VERSION 5.8 ;
BUSBITCHARS "[]" ;
DIVIDERCHAR "/" ;
UNITS
    DATABASE MICRONS 1000 ;
END UNITS

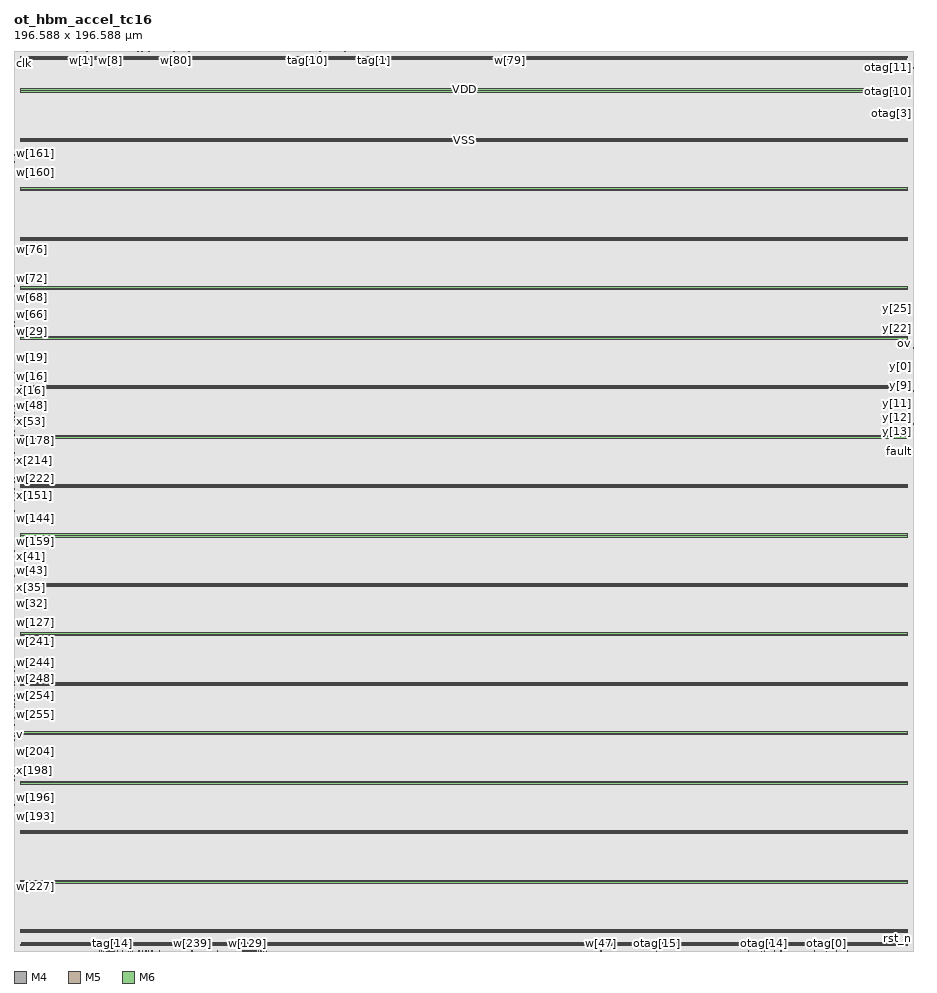
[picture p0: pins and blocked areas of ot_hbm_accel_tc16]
MACRO ot_hbm_accel_tc16
  FOREIGN ot_hbm_accel_tc16 0 0 ;
  CLASS BLOCK ;
  SIZE 196.588 BY 196.588 ;
  PIN clk
    DIRECTION INPUT ;
    USE SIGNAL ;
    PORT
      LAYER M4 ;
        RECT  0 193.824 0.084 193.848 ;
    END
  END clk
  PIN fault
    DIRECTION OUTPUT ;
    USE SIGNAL ;
    PORT
      LAYER M4 ;
        RECT  196.504 109.152 196.588 109.176 ;
    END
  END fault
  PIN first
    DIRECTION INPUT ;
    USE SIGNAL ;
    PORT
      LAYER M4 ;
        RECT  0 47.424 0.084 47.448 ;
    END
  END first
  PIN last
    DIRECTION INPUT ;
    USE SIGNAL ;
    PORT
      LAYER M4 ;
        RECT  0 47.616 0.084 47.64 ;
    END
  END last
  PIN otag[0]
    DIRECTION OUTPUT ;
    USE SIGNAL ;
    PORT
      LAYER M5 ;
        RECT  177.408 0 177.432 0.084 ;
    END
  END otag[0]
  PIN otag[10]
    DIRECTION OUTPUT ;
    USE SIGNAL ;
    PORT
      LAYER M4 ;
        RECT  196.504 187.68 196.588 187.704 ;
    END
  END otag[10]
  PIN otag[11]
    DIRECTION OUTPUT ;
    USE SIGNAL ;
    PORT
      LAYER M4 ;
        RECT  196.504 192.864 196.588 192.888 ;
    END
  END otag[11]
  PIN otag[12]
    DIRECTION OUTPUT ;
    USE SIGNAL ;
    PORT
      LAYER M5 ;
        RECT  174.816 0 174.84 0.084 ;
    END
  END otag[12]
  PIN otag[13]
    DIRECTION OUTPUT ;
    USE SIGNAL ;
    PORT
      LAYER M5 ;
        RECT  179.712 0 179.736 0.084 ;
    END
  END otag[13]
  PIN otag[14]
    DIRECTION OUTPUT ;
    USE SIGNAL ;
    PORT
      LAYER M5 ;
        RECT  163.872 0 163.896 0.084 ;
    END
  END otag[14]
  PIN otag[15]
    DIRECTION OUTPUT ;
    USE SIGNAL ;
    PORT
      LAYER M5 ;
        RECT  140.352 0 140.376 0.084 ;
    END
  END otag[15]
  PIN otag[1]
    DIRECTION OUTPUT ;
    USE SIGNAL ;
    PORT
      LAYER M4 ;
        RECT  196.504 192.768 196.588 192.792 ;
    END
  END otag[1]
  PIN otag[2]
    DIRECTION OUTPUT ;
    USE SIGNAL ;
    PORT
      LAYER M5 ;
        RECT  188.544 196.504 188.568 196.588 ;
    END
  END otag[2]
  PIN otag[3]
    DIRECTION OUTPUT ;
    USE SIGNAL ;
    PORT
      LAYER M4 ;
        RECT  196.504 182.88 196.588 182.904 ;
    END
  END otag[3]
  PIN otag[4]
    DIRECTION OUTPUT ;
    USE SIGNAL ;
    PORT
      LAYER M5 ;
        RECT  163.2 0 163.224 0.084 ;
    END
  END otag[4]
  PIN otag[5]
    DIRECTION OUTPUT ;
    USE SIGNAL ;
    PORT
      LAYER M4 ;
        RECT  196.504 186.432 196.588 186.456 ;
    END
  END otag[5]
  PIN otag[6]
    DIRECTION OUTPUT ;
    USE SIGNAL ;
    PORT
      LAYER M5 ;
        RECT  166.08 0 166.104 0.084 ;
    END
  END otag[6]
  PIN otag[7]
    DIRECTION OUTPUT ;
    USE SIGNAL ;
    PORT
      LAYER M5 ;
        RECT  182.112 0 182.136 0.084 ;
    END
  END otag[7]
  PIN otag[8]
    DIRECTION OUTPUT ;
    USE SIGNAL ;
    PORT
      LAYER M5 ;
        RECT  181.824 196.504 181.848 196.588 ;
    END
  END otag[8]
  PIN otag[9]
    DIRECTION OUTPUT ;
    USE SIGNAL ;
    PORT
      LAYER M5 ;
        RECT  160.512 0 160.536 0.084 ;
    END
  END otag[9]
  PIN ov
    DIRECTION OUTPUT ;
    USE SIGNAL ;
    PORT
      LAYER M4 ;
        RECT  196.504 132.672 196.588 132.696 ;
    END
  END ov
  PIN rst_n
    DIRECTION INPUT ;
    USE SIGNAL ;
    PORT
      LAYER M4 ;
        RECT  196.504 2.688 196.588 2.712 ;
    END
  END rst_n
  PIN tag[0]
    DIRECTION INPUT ;
    USE SIGNAL ;
    PORT
      LAYER M5 ;
        RECT  50.208 0 50.232 0.084 ;
    END
  END tag[0]
  PIN tag[10]
    DIRECTION INPUT ;
    USE SIGNAL ;
    PORT
      LAYER M5 ;
        RECT  64.128 196.504 64.152 196.588 ;
    END
  END tag[10]
  PIN tag[11]
    DIRECTION INPUT ;
    USE SIGNAL ;
    PORT
      LAYER M5 ;
        RECT  72.288 196.504 72.312 196.588 ;
    END
  END tag[11]
  PIN tag[12]
    DIRECTION INPUT ;
    USE SIGNAL ;
    PORT
      LAYER M5 ;
        RECT  19.488 0 19.512 0.084 ;
    END
  END tag[12]
  PIN tag[13]
    DIRECTION INPUT ;
    USE SIGNAL ;
    PORT
      LAYER M4 ;
        RECT  0 105.12 0.084 105.144 ;
    END
  END tag[13]
  PIN tag[14]
    DIRECTION INPUT ;
    USE SIGNAL ;
    PORT
      LAYER M5 ;
        RECT  21.6 0 21.624 0.084 ;
    END
  END tag[14]
  PIN tag[15]
    DIRECTION INPUT ;
    USE SIGNAL ;
    PORT
      LAYER M5 ;
        RECT  18.72 0 18.744 0.084 ;
    END
  END tag[15]
  PIN tag[1]
    DIRECTION INPUT ;
    USE SIGNAL ;
    PORT
      LAYER M5 ;
        RECT  78.528 196.504 78.552 196.588 ;
    END
  END tag[1]
  PIN tag[2]
    DIRECTION INPUT ;
    USE SIGNAL ;
    PORT
      LAYER M5 ;
        RECT  76.032 196.504 76.056 196.588 ;
    END
  END tag[2]
  PIN tag[3]
    DIRECTION INPUT ;
    USE SIGNAL ;
    PORT
      LAYER M5 ;
        RECT  74.496 196.504 74.52 196.588 ;
    END
  END tag[3]
  PIN tag[4]
    DIRECTION INPUT ;
    USE SIGNAL ;
    PORT
      LAYER M5 ;
        RECT  44.352 0 44.376 0.084 ;
    END
  END tag[4]
  PIN tag[5]
    DIRECTION INPUT ;
    USE SIGNAL ;
    PORT
      LAYER M5 ;
        RECT  74.976 196.504 75 196.588 ;
    END
  END tag[5]
  PIN tag[6]
    DIRECTION INPUT ;
    USE SIGNAL ;
    PORT
      LAYER M4 ;
        RECT  0 102.24 0.084 102.264 ;
    END
  END tag[6]
  PIN tag[7]
    DIRECTION INPUT ;
    USE SIGNAL ;
    PORT
      LAYER M5 ;
        RECT  19.008 0 19.032 0.084 ;
    END
  END tag[7]
  PIN tag[8]
    DIRECTION INPUT ;
    USE SIGNAL ;
    PORT
      LAYER M5 ;
        RECT  75.744 196.504 75.768 196.588 ;
    END
  END tag[8]
  PIN tag[9]
    DIRECTION INPUT ;
    USE SIGNAL ;
    PORT
      LAYER M5 ;
        RECT  22.56 0 22.584 0.084 ;
    END
  END tag[9]
  PIN v
    DIRECTION INPUT ;
    USE SIGNAL ;
    PORT
      LAYER M4 ;
        RECT  0 47.328 0.084 47.352 ;
    END
  END v
  PIN w[0]
    DIRECTION INPUT ;
    USE SIGNAL ;
    PORT
      LAYER M5 ;
        RECT  15.264 196.504 15.288 196.588 ;
    END
  END w[0]
  PIN w[100]
    DIRECTION INPUT ;
    USE SIGNAL ;
    PORT
      LAYER M4 ;
        RECT  0 51.744 0.084 51.768 ;
    END
  END w[100]
  PIN w[101]
    DIRECTION INPUT ;
    USE SIGNAL ;
    PORT
      LAYER M4 ;
        RECT  0 52.608 0.084 52.632 ;
    END
  END w[101]
  PIN w[102]
    DIRECTION INPUT ;
    USE SIGNAL ;
    PORT
      LAYER M4 ;
        RECT  0 50.304 0.084 50.328 ;
    END
  END w[102]
  PIN w[103]
    DIRECTION INPUT ;
    USE SIGNAL ;
    PORT
      LAYER M4 ;
        RECT  0 52.8 0.084 52.824 ;
    END
  END w[103]
  PIN w[104]
    DIRECTION INPUT ;
    USE SIGNAL ;
    PORT
      LAYER M4 ;
        RECT  0 53.664 0.084 53.688 ;
    END
  END w[104]
  PIN w[105]
    DIRECTION INPUT ;
    USE SIGNAL ;
    PORT
      LAYER M4 ;
        RECT  0 52.128 0.084 52.152 ;
    END
  END w[105]
  PIN w[106]
    DIRECTION INPUT ;
    USE SIGNAL ;
    PORT
      LAYER M4 ;
        RECT  0 52.224 0.084 52.248 ;
    END
  END w[106]
  PIN w[107]
    DIRECTION INPUT ;
    USE SIGNAL ;
    PORT
      LAYER M4 ;
        RECT  0 53.088 0.084 53.112 ;
    END
  END w[107]
  PIN w[108]
    DIRECTION INPUT ;
    USE SIGNAL ;
    PORT
      LAYER M4 ;
        RECT  0 53.28 0.084 53.304 ;
    END
  END w[108]
  PIN w[109]
    DIRECTION INPUT ;
    USE SIGNAL ;
    PORT
      LAYER M4 ;
        RECT  0 53.184 0.084 53.208 ;
    END
  END w[109]
  PIN w[10]
    DIRECTION INPUT ;
    USE SIGNAL ;
    PORT
      LAYER M5 ;
        RECT  22.656 196.504 22.68 196.588 ;
    END
  END w[10]
  PIN w[110]
    DIRECTION INPUT ;
    USE SIGNAL ;
    PORT
      LAYER M4 ;
        RECT  0 53.376 0.084 53.4 ;
    END
  END w[110]
  PIN w[111]
    DIRECTION INPUT ;
    USE SIGNAL ;
    PORT
      LAYER M4 ;
        RECT  0 58.752 0.084 58.776 ;
    END
  END w[111]
  PIN w[112]
    DIRECTION INPUT ;
    USE SIGNAL ;
    PORT
      LAYER M4 ;
        RECT  0 46.08 0.084 46.104 ;
    END
  END w[112]
  PIN w[113]
    DIRECTION INPUT ;
    USE SIGNAL ;
    PORT
      LAYER M4 ;
        RECT  0 48.864 0.084 48.888 ;
    END
  END w[113]
  PIN w[114]
    DIRECTION INPUT ;
    USE SIGNAL ;
    PORT
      LAYER M4 ;
        RECT  0 46.176 0.084 46.2 ;
    END
  END w[114]
  PIN w[115]
    DIRECTION INPUT ;
    USE SIGNAL ;
    PORT
      LAYER M4 ;
        RECT  0 46.944 0.084 46.968 ;
    END
  END w[115]
  PIN w[116]
    DIRECTION INPUT ;
    USE SIGNAL ;
    PORT
      LAYER M4 ;
        RECT  0 50.88 0.084 50.904 ;
    END
  END w[116]
  PIN w[117]
    DIRECTION INPUT ;
    USE SIGNAL ;
    PORT
      LAYER M4 ;
        RECT  0 48.096 0.084 48.12 ;
    END
  END w[117]
  PIN w[118]
    DIRECTION INPUT ;
    USE SIGNAL ;
    PORT
      LAYER M4 ;
        RECT  0 49.344 0.084 49.368 ;
    END
  END w[118]
  PIN w[119]
    DIRECTION INPUT ;
    USE SIGNAL ;
    PORT
      LAYER M4 ;
        RECT  0 50.4 0.084 50.424 ;
    END
  END w[119]
  PIN w[11]
    DIRECTION INPUT ;
    USE SIGNAL ;
    PORT
      LAYER M5 ;
        RECT  22.752 196.504 22.776 196.588 ;
    END
  END w[11]
  PIN w[120]
    DIRECTION INPUT ;
    USE SIGNAL ;
    PORT
      LAYER M4 ;
        RECT  0 52.032 0.084 52.056 ;
    END
  END w[120]
  PIN w[121]
    DIRECTION INPUT ;
    USE SIGNAL ;
    PORT
      LAYER M4 ;
        RECT  0 52.32 0.084 52.344 ;
    END
  END w[121]
  PIN w[122]
    DIRECTION INPUT ;
    USE SIGNAL ;
    PORT
      LAYER M4 ;
        RECT  0 52.992 0.084 53.016 ;
    END
  END w[122]
  PIN w[123]
    DIRECTION INPUT ;
    USE SIGNAL ;
    PORT
      LAYER M4 ;
        RECT  0 52.896 0.084 52.92 ;
    END
  END w[123]
  PIN w[124]
    DIRECTION INPUT ;
    USE SIGNAL ;
    PORT
      LAYER M4 ;
        RECT  0 54.336 0.084 54.36 ;
    END
  END w[124]
  PIN w[125]
    DIRECTION INPUT ;
    USE SIGNAL ;
    PORT
      LAYER M4 ;
        RECT  0 54.24 0.084 54.264 ;
    END
  END w[125]
  PIN w[126]
    DIRECTION INPUT ;
    USE SIGNAL ;
    PORT
      LAYER M4 ;
        RECT  0 54.432 0.084 54.456 ;
    END
  END w[126]
  PIN w[127]
    DIRECTION INPUT ;
    USE SIGNAL ;
    PORT
      LAYER M4 ;
        RECT  0 71.712 0.084 71.736 ;
    END
  END w[127]
  PIN w[128]
    DIRECTION INPUT ;
    USE SIGNAL ;
    PORT
      LAYER M5 ;
        RECT  51.36 0 51.384 0.084 ;
    END
  END w[128]
  PIN w[129]
    DIRECTION INPUT ;
    USE SIGNAL ;
    PORT
      LAYER M5 ;
        RECT  51.072 0 51.096 0.084 ;
    END
  END w[129]
  PIN w[12]
    DIRECTION INPUT ;
    USE SIGNAL ;
    PORT
      LAYER M5 ;
        RECT  20.448 196.504 20.472 196.588 ;
    END
  END w[12]
  PIN w[130]
    DIRECTION INPUT ;
    USE SIGNAL ;
    PORT
      LAYER M5 ;
        RECT  50.016 0 50.04 0.084 ;
    END
  END w[130]
  PIN w[131]
    DIRECTION INPUT ;
    USE SIGNAL ;
    PORT
      LAYER M5 ;
        RECT  50.592 0 50.616 0.084 ;
    END
  END w[131]
  PIN w[132]
    DIRECTION INPUT ;
    USE SIGNAL ;
    PORT
      LAYER M5 ;
        RECT  50.4 0 50.424 0.084 ;
    END
  END w[132]
  PIN w[133]
    DIRECTION INPUT ;
    USE SIGNAL ;
    PORT
      LAYER M5 ;
        RECT  50.496 0 50.52 0.084 ;
    END
  END w[133]
  PIN w[134]
    DIRECTION INPUT ;
    USE SIGNAL ;
    PORT
      LAYER M5 ;
        RECT  50.784 0 50.808 0.084 ;
    END
  END w[134]
  PIN w[135]
    DIRECTION INPUT ;
    USE SIGNAL ;
    PORT
      LAYER M5 ;
        RECT  51.648 0 51.672 0.084 ;
    END
  END w[135]
  PIN w[136]
    DIRECTION INPUT ;
    USE SIGNAL ;
    PORT
      LAYER M5 ;
        RECT  52.032 0 52.056 0.084 ;
    END
  END w[136]
  PIN w[137]
    DIRECTION INPUT ;
    USE SIGNAL ;
    PORT
      LAYER M5 ;
        RECT  52.416 0 52.44 0.084 ;
    END
  END w[137]
  PIN w[138]
    DIRECTION INPUT ;
    USE SIGNAL ;
    PORT
      LAYER M5 ;
        RECT  52.128 0 52.152 0.084 ;
    END
  END w[138]
  PIN w[139]
    DIRECTION INPUT ;
    USE SIGNAL ;
    PORT
      LAYER M5 ;
        RECT  51.936 0 51.96 0.084 ;
    END
  END w[139]
  PIN w[13]
    DIRECTION INPUT ;
    USE SIGNAL ;
    PORT
      LAYER M5 ;
        RECT  20.256 196.504 20.28 196.588 ;
    END
  END w[13]
  PIN w[140]
    DIRECTION INPUT ;
    USE SIGNAL ;
    PORT
      LAYER M5 ;
        RECT  54.432 0 54.456 0.084 ;
    END
  END w[140]
  PIN w[141]
    DIRECTION INPUT ;
    USE SIGNAL ;
    PORT
      LAYER M5 ;
        RECT  53.376 0 53.4 0.084 ;
    END
  END w[141]
  PIN w[142]
    DIRECTION INPUT ;
    USE SIGNAL ;
    PORT
      LAYER M5 ;
        RECT  53.472 0 53.496 0.084 ;
    END
  END w[142]
  PIN w[143]
    DIRECTION INPUT ;
    USE SIGNAL ;
    PORT
      LAYER M5 ;
        RECT  167.616 0 167.64 0.084 ;
    END
  END w[143]
  PIN w[144]
    DIRECTION INPUT ;
    USE SIGNAL ;
    PORT
      LAYER M4 ;
        RECT  0 94.368 0.084 94.392 ;
    END
  END w[144]
  PIN w[145]
    DIRECTION INPUT ;
    USE SIGNAL ;
    PORT
      LAYER M4 ;
        RECT  0 97.92 0.084 97.944 ;
    END
  END w[145]
  PIN w[146]
    DIRECTION INPUT ;
    USE SIGNAL ;
    PORT
      LAYER M4 ;
        RECT  0 99.072 0.084 99.096 ;
    END
  END w[146]
  PIN w[147]
    DIRECTION INPUT ;
    USE SIGNAL ;
    PORT
      LAYER M4 ;
        RECT  0 96.48 0.084 96.504 ;
    END
  END w[147]
  PIN w[148]
    DIRECTION INPUT ;
    USE SIGNAL ;
    PORT
      LAYER M4 ;
        RECT  0 98.976 0.084 99 ;
    END
  END w[148]
  PIN w[149]
    DIRECTION INPUT ;
    USE SIGNAL ;
    PORT
      LAYER M4 ;
        RECT  0 96.768 0.084 96.792 ;
    END
  END w[149]
  PIN w[14]
    DIRECTION INPUT ;
    USE SIGNAL ;
    PORT
      LAYER M5 ;
        RECT  20.352 196.504 20.376 196.588 ;
    END
  END w[14]
  PIN w[150]
    DIRECTION INPUT ;
    USE SIGNAL ;
    PORT
      LAYER M4 ;
        RECT  0 99.456 0.084 99.48 ;
    END
  END w[150]
  PIN w[151]
    DIRECTION INPUT ;
    USE SIGNAL ;
    PORT
      LAYER M4 ;
        RECT  0 101.088 0.084 101.112 ;
    END
  END w[151]
  PIN w[152]
    DIRECTION INPUT ;
    USE SIGNAL ;
    PORT
      LAYER M4 ;
        RECT  0 100.896 0.084 100.92 ;
    END
  END w[152]
  PIN w[153]
    DIRECTION INPUT ;
    USE SIGNAL ;
    PORT
      LAYER M4 ;
        RECT  0 100.8 0.084 100.824 ;
    END
  END w[153]
  PIN w[154]
    DIRECTION INPUT ;
    USE SIGNAL ;
    PORT
      LAYER M4 ;
        RECT  0 100.992 0.084 101.016 ;
    END
  END w[154]
  PIN w[155]
    DIRECTION INPUT ;
    USE SIGNAL ;
    PORT
      LAYER M4 ;
        RECT  0 101.856 0.084 101.88 ;
    END
  END w[155]
  PIN w[156]
    DIRECTION INPUT ;
    USE SIGNAL ;
    PORT
      LAYER M4 ;
        RECT  0 102.144 0.084 102.168 ;
    END
  END w[156]
  PIN w[157]
    DIRECTION INPUT ;
    USE SIGNAL ;
    PORT
      LAYER M4 ;
        RECT  0 102.528 0.084 102.552 ;
    END
  END w[157]
  PIN w[158]
    DIRECTION INPUT ;
    USE SIGNAL ;
    PORT
      LAYER M4 ;
        RECT  0 102.432 0.084 102.456 ;
    END
  END w[158]
  PIN w[159]
    DIRECTION INPUT ;
    USE SIGNAL ;
    PORT
      LAYER M4 ;
        RECT  0 89.472 0.084 89.496 ;
    END
  END w[159]
  PIN w[15]
    DIRECTION INPUT ;
    USE SIGNAL ;
    PORT
      LAYER M5 ;
        RECT  39.936 196.504 39.96 196.588 ;
    END
  END w[15]
  PIN w[160]
    DIRECTION INPUT ;
    USE SIGNAL ;
    PORT
      LAYER M4 ;
        RECT  0 170.016 0.084 170.04 ;
    END
  END w[160]
  PIN w[161]
    DIRECTION INPUT ;
    USE SIGNAL ;
    PORT
      LAYER M4 ;
        RECT  0 172.512 0.084 172.536 ;
    END
  END w[161]
  PIN w[162]
    DIRECTION INPUT ;
    USE SIGNAL ;
    PORT
      LAYER M4 ;
        RECT  0 172.128 0.084 172.152 ;
    END
  END w[162]
  PIN w[163]
    DIRECTION INPUT ;
    USE SIGNAL ;
    PORT
      LAYER M4 ;
        RECT  0 172.224 0.084 172.248 ;
    END
  END w[163]
  PIN w[164]
    DIRECTION INPUT ;
    USE SIGNAL ;
    PORT
      LAYER M4 ;
        RECT  0 172.32 0.084 172.344 ;
    END
  END w[164]
  PIN w[165]
    DIRECTION INPUT ;
    USE SIGNAL ;
    PORT
      LAYER M4 ;
        RECT  0 170.976 0.084 171 ;
    END
  END w[165]
  PIN w[166]
    DIRECTION INPUT ;
    USE SIGNAL ;
    PORT
      LAYER M4 ;
        RECT  0 171.168 0.084 171.192 ;
    END
  END w[166]
  PIN w[167]
    DIRECTION INPUT ;
    USE SIGNAL ;
    PORT
      LAYER M4 ;
        RECT  0 172.032 0.084 172.056 ;
    END
  END w[167]
  PIN w[168]
    DIRECTION INPUT ;
    USE SIGNAL ;
    PORT
      LAYER M5 ;
        RECT  27.072 196.504 27.096 196.588 ;
    END
  END w[168]
  PIN w[169]
    DIRECTION INPUT ;
    USE SIGNAL ;
    PORT
      LAYER M5 ;
        RECT  26.976 196.504 27 196.588 ;
    END
  END w[169]
  PIN w[16]
    DIRECTION INPUT ;
    USE SIGNAL ;
    PORT
      LAYER M4 ;
        RECT  0 125.568 0.084 125.592 ;
    END
  END w[16]
  PIN w[170]
    DIRECTION INPUT ;
    USE SIGNAL ;
    PORT
      LAYER M5 ;
        RECT  27.648 196.504 27.672 196.588 ;
    END
  END w[170]
  PIN w[171]
    DIRECTION INPUT ;
    USE SIGNAL ;
    PORT
      LAYER M5 ;
        RECT  27.552 196.504 27.576 196.588 ;
    END
  END w[171]
  PIN w[172]
    DIRECTION INPUT ;
    USE SIGNAL ;
    PORT
      LAYER M5 ;
        RECT  29.376 196.504 29.4 196.588 ;
    END
  END w[172]
  PIN w[173]
    DIRECTION INPUT ;
    USE SIGNAL ;
    PORT
      LAYER M5 ;
        RECT  29.472 196.504 29.496 196.588 ;
    END
  END w[173]
  PIN w[174]
    DIRECTION INPUT ;
    USE SIGNAL ;
    PORT
      LAYER M5 ;
        RECT  30.528 196.504 30.552 196.588 ;
    END
  END w[174]
  PIN w[175]
    DIRECTION INPUT ;
    USE SIGNAL ;
    PORT
      LAYER M5 ;
        RECT  77.952 196.504 77.976 196.588 ;
    END
  END w[175]
  PIN w[176]
    DIRECTION INPUT ;
    USE SIGNAL ;
    PORT
      LAYER M4 ;
        RECT  0 113.28 0.084 113.304 ;
    END
  END w[176]
  PIN w[177]
    DIRECTION INPUT ;
    USE SIGNAL ;
    PORT
      LAYER M4 ;
        RECT  0 111.744 0.084 111.768 ;
    END
  END w[177]
  PIN w[178]
    DIRECTION INPUT ;
    USE SIGNAL ;
    PORT
      LAYER M4 ;
        RECT  0 111.552 0.084 111.576 ;
    END
  END w[178]
  PIN w[179]
    DIRECTION INPUT ;
    USE SIGNAL ;
    PORT
      LAYER M4 ;
        RECT  0 109.152 0.084 109.176 ;
    END
  END w[179]
  PIN w[17]
    DIRECTION INPUT ;
    USE SIGNAL ;
    PORT
      LAYER M4 ;
        RECT  0 125.952 0.084 125.976 ;
    END
  END w[17]
  PIN w[180]
    DIRECTION INPUT ;
    USE SIGNAL ;
    PORT
      LAYER M4 ;
        RECT  0 108.768 0.084 108.792 ;
    END
  END w[180]
  PIN w[181]
    DIRECTION INPUT ;
    USE SIGNAL ;
    PORT
      LAYER M4 ;
        RECT  0 109.728 0.084 109.752 ;
    END
  END w[181]
  PIN w[182]
    DIRECTION INPUT ;
    USE SIGNAL ;
    PORT
      LAYER M4 ;
        RECT  0 112.992 0.084 113.016 ;
    END
  END w[182]
  PIN w[183]
    DIRECTION INPUT ;
    USE SIGNAL ;
    PORT
      LAYER M4 ;
        RECT  0 112.896 0.084 112.92 ;
    END
  END w[183]
  PIN w[184]
    DIRECTION INPUT ;
    USE SIGNAL ;
    PORT
      LAYER M4 ;
        RECT  0 114.432 0.084 114.456 ;
    END
  END w[184]
  PIN w[185]
    DIRECTION INPUT ;
    USE SIGNAL ;
    PORT
      LAYER M4 ;
        RECT  0 114.048 0.084 114.072 ;
    END
  END w[185]
  PIN w[186]
    DIRECTION INPUT ;
    USE SIGNAL ;
    PORT
      LAYER M4 ;
        RECT  0 114.336 0.084 114.36 ;
    END
  END w[186]
  PIN w[187]
    DIRECTION INPUT ;
    USE SIGNAL ;
    PORT
      LAYER M4 ;
        RECT  0 114.528 0.084 114.552 ;
    END
  END w[187]
  PIN w[188]
    DIRECTION INPUT ;
    USE SIGNAL ;
    PORT
      LAYER M4 ;
        RECT  0 113.856 0.084 113.88 ;
    END
  END w[188]
  PIN w[189]
    DIRECTION INPUT ;
    USE SIGNAL ;
    PORT
      LAYER M4 ;
        RECT  0 113.568 0.084 113.592 ;
    END
  END w[189]
  PIN w[18]
    DIRECTION INPUT ;
    USE SIGNAL ;
    PORT
      LAYER M4 ;
        RECT  0 126.24 0.084 126.264 ;
    END
  END w[18]
  PIN w[190]
    DIRECTION INPUT ;
    USE SIGNAL ;
    PORT
      LAYER M4 ;
        RECT  0 112.8 0.084 112.824 ;
    END
  END w[190]
  PIN w[191]
    DIRECTION INPUT ;
    USE SIGNAL ;
    PORT
      LAYER M4 ;
        RECT  0 126.144 0.084 126.168 ;
    END
  END w[191]
  PIN w[192]
    DIRECTION INPUT ;
    USE SIGNAL ;
    PORT
      LAYER M4 ;
        RECT  0 30.624 0.084 30.648 ;
    END
  END w[192]
  PIN w[193]
    DIRECTION INPUT ;
    USE SIGNAL ;
    PORT
      LAYER M4 ;
        RECT  0 29.376 0.084 29.4 ;
    END
  END w[193]
  PIN w[194]
    DIRECTION INPUT ;
    USE SIGNAL ;
    PORT
      LAYER M4 ;
        RECT  0 29.856 0.084 29.88 ;
    END
  END w[194]
  PIN w[195]
    DIRECTION INPUT ;
    USE SIGNAL ;
    PORT
      LAYER M4 ;
        RECT  0 29.28 0.084 29.304 ;
    END
  END w[195]
  PIN w[196]
    DIRECTION INPUT ;
    USE SIGNAL ;
    PORT
      LAYER M4 ;
        RECT  0 31.872 0.084 31.896 ;
    END
  END w[196]
  PIN w[197]
    DIRECTION INPUT ;
    USE SIGNAL ;
    PORT
      LAYER M4 ;
        RECT  0 32.928 0.084 32.952 ;
    END
  END w[197]
  PIN w[198]
    DIRECTION INPUT ;
    USE SIGNAL ;
    PORT
      LAYER M4 ;
        RECT  0 33.024 0.084 33.048 ;
    END
  END w[198]
  PIN w[199]
    DIRECTION INPUT ;
    USE SIGNAL ;
    PORT
      LAYER M4 ;
        RECT  0 34.368 0.084 34.392 ;
    END
  END w[199]
  PIN w[19]
    DIRECTION INPUT ;
    USE SIGNAL ;
    PORT
      LAYER M4 ;
        RECT  0 127.968 0.084 127.992 ;
    END
  END w[19]
  PIN w[1]
    DIRECTION INPUT ;
    USE SIGNAL ;
    PORT
      LAYER M5 ;
        RECT  14.784 196.504 14.808 196.588 ;
    END
  END w[1]
  PIN w[200]
    DIRECTION INPUT ;
    USE SIGNAL ;
    PORT
      LAYER M4 ;
        RECT  0 35.04 0.084 35.064 ;
    END
  END w[200]
  PIN w[201]
    DIRECTION INPUT ;
    USE SIGNAL ;
    PORT
      LAYER M4 ;
        RECT  0 36.192 0.084 36.216 ;
    END
  END w[201]
  PIN w[202]
    DIRECTION INPUT ;
    USE SIGNAL ;
    PORT
      LAYER M4 ;
        RECT  0 36.096 0.084 36.12 ;
    END
  END w[202]
  PIN w[203]
    DIRECTION INPUT ;
    USE SIGNAL ;
    PORT
      LAYER M4 ;
        RECT  0 37.056 0.084 37.08 ;
    END
  END w[203]
  PIN w[204]
    DIRECTION INPUT ;
    USE SIGNAL ;
    PORT
      LAYER M4 ;
        RECT  0 41.76 0.084 41.784 ;
    END
  END w[204]
  PIN w[205]
    DIRECTION INPUT ;
    USE SIGNAL ;
    PORT
      LAYER M4 ;
        RECT  0 42.432 0.084 42.456 ;
    END
  END w[205]
  PIN w[206]
    DIRECTION INPUT ;
    USE SIGNAL ;
    PORT
      LAYER M4 ;
        RECT  0 42.528 0.084 42.552 ;
    END
  END w[206]
  PIN w[207]
    DIRECTION INPUT ;
    USE SIGNAL ;
    PORT
      LAYER M4 ;
        RECT  0 37.344 0.084 37.368 ;
    END
  END w[207]
  PIN w[208]
    DIRECTION INPUT ;
    USE SIGNAL ;
    PORT
      LAYER M4 ;
        RECT  0 104.448 0.084 104.472 ;
    END
  END w[208]
  PIN w[209]
    DIRECTION INPUT ;
    USE SIGNAL ;
    PORT
      LAYER M4 ;
        RECT  0 104.736 0.084 104.76 ;
    END
  END w[209]
  PIN w[20]
    DIRECTION INPUT ;
    USE SIGNAL ;
    PORT
      LAYER M4 ;
        RECT  0 126.912 0.084 126.936 ;
    END
  END w[20]
  PIN w[210]
    DIRECTION INPUT ;
    USE SIGNAL ;
    PORT
      LAYER M4 ;
        RECT  0 105.408 0.084 105.432 ;
    END
  END w[210]
  PIN w[211]
    DIRECTION INPUT ;
    USE SIGNAL ;
    PORT
      LAYER M4 ;
        RECT  0 106.176 0.084 106.2 ;
    END
  END w[211]
  PIN w[212]
    DIRECTION INPUT ;
    USE SIGNAL ;
    PORT
      LAYER M4 ;
        RECT  0 101.952 0.084 101.976 ;
    END
  END w[212]
  PIN w[213]
    DIRECTION INPUT ;
    USE SIGNAL ;
    PORT
      LAYER M4 ;
        RECT  0 105.504 0.084 105.528 ;
    END
  END w[213]
  PIN w[214]
    DIRECTION INPUT ;
    USE SIGNAL ;
    PORT
      LAYER M4 ;
        RECT  0 105.216 0.084 105.24 ;
    END
  END w[214]
  PIN w[215]
    DIRECTION INPUT ;
    USE SIGNAL ;
    PORT
      LAYER M4 ;
        RECT  0 102.624 0.084 102.648 ;
    END
  END w[215]
  PIN w[216]
    DIRECTION INPUT ;
    USE SIGNAL ;
    PORT
      LAYER M4 ;
        RECT  0 103.008 0.084 103.032 ;
    END
  END w[216]
  PIN w[217]
    DIRECTION INPUT ;
    USE SIGNAL ;
    PORT
      LAYER M4 ;
        RECT  0 103.488 0.084 103.512 ;
    END
  END w[217]
  PIN w[218]
    DIRECTION INPUT ;
    USE SIGNAL ;
    PORT
      LAYER M4 ;
        RECT  0 102.72 0.084 102.744 ;
    END
  END w[218]
  PIN w[219]
    DIRECTION INPUT ;
    USE SIGNAL ;
    PORT
      LAYER M4 ;
        RECT  0 102.816 0.084 102.84 ;
    END
  END w[219]
  PIN w[21]
    DIRECTION INPUT ;
    USE SIGNAL ;
    PORT
      LAYER M4 ;
        RECT  0 128.928 0.084 128.952 ;
    END
  END w[21]
  PIN w[220]
    DIRECTION INPUT ;
    USE SIGNAL ;
    PORT
      LAYER M4 ;
        RECT  0 103.584 0.084 103.608 ;
    END
  END w[220]
  PIN w[221]
    DIRECTION INPUT ;
    USE SIGNAL ;
    PORT
      LAYER M4 ;
        RECT  0 103.104 0.084 103.128 ;
    END
  END w[221]
  PIN w[222]
    DIRECTION INPUT ;
    USE SIGNAL ;
    PORT
      LAYER M4 ;
        RECT  0 103.296 0.084 103.32 ;
    END
  END w[222]
  PIN w[223]
    DIRECTION INPUT ;
    USE SIGNAL ;
    PORT
      LAYER M4 ;
        RECT  0 102.912 0.084 102.936 ;
    END
  END w[223]
  PIN w[224]
    DIRECTION INPUT ;
    USE SIGNAL ;
    PORT
      LAYER M5 ;
        RECT  21.504 0 21.528 0.084 ;
    END
  END w[224]
  PIN w[225]
    DIRECTION INPUT ;
    USE SIGNAL ;
    PORT
      LAYER M5 ;
        RECT  21.888 0 21.912 0.084 ;
    END
  END w[225]
  PIN w[226]
    DIRECTION INPUT ;
    USE SIGNAL ;
    PORT
      LAYER M5 ;
        RECT  21.024 0 21.048 0.084 ;
    END
  END w[226]
  PIN w[227]
    DIRECTION INPUT ;
    USE SIGNAL ;
    PORT
      LAYER M4 ;
        RECT  0 14.112 0.084 14.136 ;
    END
  END w[227]
  PIN w[228]
    DIRECTION INPUT ;
    USE SIGNAL ;
    PORT
      LAYER M5 ;
        RECT  23.616 0 23.64 0.084 ;
    END
  END w[228]
  PIN w[229]
    DIRECTION INPUT ;
    USE SIGNAL ;
    PORT
      LAYER M5 ;
        RECT  21.696 0 21.72 0.084 ;
    END
  END w[229]
  PIN w[22]
    DIRECTION INPUT ;
    USE SIGNAL ;
    PORT
      LAYER M4 ;
        RECT  0 129.504 0.084 129.528 ;
    END
  END w[22]
  PIN w[230]
    DIRECTION INPUT ;
    USE SIGNAL ;
    PORT
      LAYER M5 ;
        RECT  22.656 0 22.68 0.084 ;
    END
  END w[230]
  PIN w[231]
    DIRECTION INPUT ;
    USE SIGNAL ;
    PORT
      LAYER M5 ;
        RECT  25.056 0 25.08 0.084 ;
    END
  END w[231]
  PIN w[232]
    DIRECTION INPUT ;
    USE SIGNAL ;
    PORT
      LAYER M5 ;
        RECT  25.824 0 25.848 0.084 ;
    END
  END w[232]
  PIN w[233]
    DIRECTION INPUT ;
    USE SIGNAL ;
    PORT
      LAYER M5 ;
        RECT  25.92 0 25.944 0.084 ;
    END
  END w[233]
  PIN w[234]
    DIRECTION INPUT ;
    USE SIGNAL ;
    PORT
      LAYER M5 ;
        RECT  27.264 0 27.288 0.084 ;
    END
  END w[234]
  PIN w[235]
    DIRECTION INPUT ;
    USE SIGNAL ;
    PORT
      LAYER M5 ;
        RECT  28.032 0 28.056 0.084 ;
    END
  END w[235]
  PIN w[236]
    DIRECTION INPUT ;
    USE SIGNAL ;
    PORT
      LAYER M5 ;
        RECT  28.8 0 28.824 0.084 ;
    END
  END w[236]
  PIN w[237]
    DIRECTION INPUT ;
    USE SIGNAL ;
    PORT
      LAYER M5 ;
        RECT  29.28 0 29.304 0.084 ;
    END
  END w[237]
  PIN w[238]
    DIRECTION INPUT ;
    USE SIGNAL ;
    PORT
      LAYER M5 ;
        RECT  30.24 0 30.264 0.084 ;
    END
  END w[238]
  PIN w[239]
    DIRECTION INPUT ;
    USE SIGNAL ;
    PORT
      LAYER M5 ;
        RECT  38.88 0 38.904 0.084 ;
    END
  END w[239]
  PIN w[23]
    DIRECTION INPUT ;
    USE SIGNAL ;
    PORT
      LAYER M4 ;
        RECT  0 130.368 0.084 130.392 ;
    END
  END w[23]
  PIN w[240]
    DIRECTION INPUT ;
    USE SIGNAL ;
    PORT
      LAYER M4 ;
        RECT  0 67.776 0.084 67.8 ;
    END
  END w[240]
  PIN w[241]
    DIRECTION INPUT ;
    USE SIGNAL ;
    PORT
      LAYER M4 ;
        RECT  0 67.68 0.084 67.704 ;
    END
  END w[241]
  PIN w[242]
    DIRECTION INPUT ;
    USE SIGNAL ;
    PORT
      LAYER M4 ;
        RECT  0 66.912 0.084 66.936 ;
    END
  END w[242]
  PIN w[243]
    DIRECTION INPUT ;
    USE SIGNAL ;
    PORT
      LAYER M4 ;
        RECT  0 66.528 0.084 66.552 ;
    END
  END w[243]
  PIN w[244]
    DIRECTION INPUT ;
    USE SIGNAL ;
    PORT
      LAYER M4 ;
        RECT  0 64.704 0.084 64.728 ;
    END
  END w[244]
  PIN w[245]
    DIRECTION INPUT ;
    USE SIGNAL ;
    PORT
      LAYER M4 ;
        RECT  0 65.76 0.084 65.784 ;
    END
  END w[245]
  PIN w[246]
    DIRECTION INPUT ;
    USE SIGNAL ;
    PORT
      LAYER M4 ;
        RECT  0 64.224 0.084 64.248 ;
    END
  END w[246]
  PIN w[247]
    DIRECTION INPUT ;
    USE SIGNAL ;
    PORT
      LAYER M4 ;
        RECT  0 63.168 0.084 63.192 ;
    END
  END w[247]
  PIN w[248]
    DIRECTION INPUT ;
    USE SIGNAL ;
    PORT
      LAYER M4 ;
        RECT  0 59.52 0.084 59.544 ;
    END
  END w[248]
  PIN w[249]
    DIRECTION INPUT ;
    USE SIGNAL ;
    PORT
      LAYER M4 ;
        RECT  0 59.424 0.084 59.448 ;
    END
  END w[249]
  PIN w[24]
    DIRECTION INPUT ;
    USE SIGNAL ;
    PORT
      LAYER M4 ;
        RECT  0 131.52 0.084 131.544 ;
    END
  END w[24]
  PIN w[250]
    DIRECTION INPUT ;
    USE SIGNAL ;
    PORT
      LAYER M4 ;
        RECT  0 58.464 0.084 58.488 ;
    END
  END w[250]
  PIN w[251]
    DIRECTION INPUT ;
    USE SIGNAL ;
    PORT
      LAYER M4 ;
        RECT  0 58.56 0.084 58.584 ;
    END
  END w[251]
  PIN w[252]
    DIRECTION INPUT ;
    USE SIGNAL ;
    PORT
      LAYER M4 ;
        RECT  0 56.736 0.084 56.76 ;
    END
  END w[252]
  PIN w[253]
    DIRECTION INPUT ;
    USE SIGNAL ;
    PORT
      LAYER M4 ;
        RECT  0 56.64 0.084 56.664 ;
    END
  END w[253]
  PIN w[254]
    DIRECTION INPUT ;
    USE SIGNAL ;
    PORT
      LAYER M4 ;
        RECT  0 55.776 0.084 55.8 ;
    END
  END w[254]
  PIN w[255]
    DIRECTION INPUT ;
    USE SIGNAL ;
    PORT
      LAYER M4 ;
        RECT  0 51.648 0.084 51.672 ;
    END
  END w[255]
  PIN w[25]
    DIRECTION INPUT ;
    USE SIGNAL ;
    PORT
      LAYER M4 ;
        RECT  0 131.424 0.084 131.448 ;
    END
  END w[25]
  PIN w[26]
    DIRECTION INPUT ;
    USE SIGNAL ;
    PORT
      LAYER M4 ;
        RECT  0 132.672 0.084 132.696 ;
    END
  END w[26]
  PIN w[27]
    DIRECTION INPUT ;
    USE SIGNAL ;
    PORT
      LAYER M4 ;
        RECT  0 132.96 0.084 132.984 ;
    END
  END w[27]
  PIN w[28]
    DIRECTION INPUT ;
    USE SIGNAL ;
    PORT
      LAYER M4 ;
        RECT  0 135.552 0.084 135.576 ;
    END
  END w[28]
  PIN w[29]
    DIRECTION INPUT ;
    USE SIGNAL ;
    PORT
      LAYER M4 ;
        RECT  0 135.36 0.084 135.384 ;
    END
  END w[29]
  PIN w[2]
    DIRECTION INPUT ;
    USE SIGNAL ;
    PORT
      LAYER M5 ;
        RECT  14.112 196.504 14.136 196.588 ;
    END
  END w[2]
  PIN w[30]
    DIRECTION INPUT ;
    USE SIGNAL ;
    PORT
      LAYER M4 ;
        RECT  0 136.032 0.084 136.056 ;
    END
  END w[30]
  PIN w[31]
    DIRECTION INPUT ;
    USE SIGNAL ;
    PORT
      LAYER M4 ;
        RECT  0 124.32 0.084 124.344 ;
    END
  END w[31]
  PIN w[32]
    DIRECTION INPUT ;
    USE SIGNAL ;
    PORT
      LAYER M4 ;
        RECT  0 77.568 0.084 77.592 ;
    END
  END w[32]
  PIN w[33]
    DIRECTION INPUT ;
    USE SIGNAL ;
    PORT
      LAYER M4 ;
        RECT  0 81.312 0.084 81.336 ;
    END
  END w[33]
  PIN w[34]
    DIRECTION INPUT ;
    USE SIGNAL ;
    PORT
      LAYER M4 ;
        RECT  0 82.08 0.084 82.104 ;
    END
  END w[34]
  PIN w[35]
    DIRECTION INPUT ;
    USE SIGNAL ;
    PORT
      LAYER M4 ;
        RECT  0 78.528 0.084 78.552 ;
    END
  END w[35]
  PIN w[36]
    DIRECTION INPUT ;
    USE SIGNAL ;
    PORT
      LAYER M4 ;
        RECT  0 78.912 0.084 78.936 ;
    END
  END w[36]
  PIN w[37]
    DIRECTION INPUT ;
    USE SIGNAL ;
    PORT
      LAYER M4 ;
        RECT  0 78.624 0.084 78.648 ;
    END
  END w[37]
  PIN w[38]
    DIRECTION INPUT ;
    USE SIGNAL ;
    PORT
      LAYER M4 ;
        RECT  0 81.984 0.084 82.008 ;
    END
  END w[38]
  PIN w[39]
    DIRECTION INPUT ;
    USE SIGNAL ;
    PORT
      LAYER M4 ;
        RECT  0 81.216 0.084 81.24 ;
    END
  END w[39]
  PIN w[3]
    DIRECTION INPUT ;
    USE SIGNAL ;
    PORT
      LAYER M5 ;
        RECT  14.016 196.504 14.04 196.588 ;
    END
  END w[3]
  PIN w[40]
    DIRECTION INPUT ;
    USE SIGNAL ;
    PORT
      LAYER M4 ;
        RECT  0 81.6 0.084 81.624 ;
    END
  END w[40]
  PIN w[41]
    DIRECTION INPUT ;
    USE SIGNAL ;
    PORT
      LAYER M4 ;
        RECT  0 81.888 0.084 81.912 ;
    END
  END w[41]
  PIN w[42]
    DIRECTION INPUT ;
    USE SIGNAL ;
    PORT
      LAYER M4 ;
        RECT  0 82.944 0.084 82.968 ;
    END
  END w[42]
  PIN w[43]
    DIRECTION INPUT ;
    USE SIGNAL ;
    PORT
      LAYER M4 ;
        RECT  0 83.04 0.084 83.064 ;
    END
  END w[43]
  PIN w[44]
    DIRECTION INPUT ;
    USE SIGNAL ;
    PORT
      LAYER M4 ;
        RECT  0 85.152 0.084 85.176 ;
    END
  END w[44]
  PIN w[45]
    DIRECTION INPUT ;
    USE SIGNAL ;
    PORT
      LAYER M4 ;
        RECT  0 85.248 0.084 85.272 ;
    END
  END w[45]
  PIN w[46]
    DIRECTION INPUT ;
    USE SIGNAL ;
    PORT
      LAYER M4 ;
        RECT  0 87.36 0.084 87.384 ;
    END
  END w[46]
  PIN w[47]
    DIRECTION INPUT ;
    USE SIGNAL ;
    PORT
      LAYER M5 ;
        RECT  128.256 0 128.28 0.084 ;
    END
  END w[47]
  PIN w[48]
    DIRECTION INPUT ;
    USE SIGNAL ;
    PORT
      LAYER M4 ;
        RECT  0 119.04 0.084 119.064 ;
    END
  END w[48]
  PIN w[49]
    DIRECTION INPUT ;
    USE SIGNAL ;
    PORT
      LAYER M4 ;
        RECT  0 118.464 0.084 118.488 ;
    END
  END w[49]
  PIN w[4]
    DIRECTION INPUT ;
    USE SIGNAL ;
    PORT
      LAYER M5 ;
        RECT  15.168 196.504 15.192 196.588 ;
    END
  END w[4]
  PIN w[50]
    DIRECTION INPUT ;
    USE SIGNAL ;
    PORT
      LAYER M4 ;
        RECT  0 120.864 0.084 120.888 ;
    END
  END w[50]
  PIN w[51]
    DIRECTION INPUT ;
    USE SIGNAL ;
    PORT
      LAYER M4 ;
        RECT  0 121.824 0.084 121.848 ;
    END
  END w[51]
  PIN w[52]
    DIRECTION INPUT ;
    USE SIGNAL ;
    PORT
      LAYER M4 ;
        RECT  0 119.52 0.084 119.544 ;
    END
  END w[52]
  PIN w[53]
    DIRECTION INPUT ;
    USE SIGNAL ;
    PORT
      LAYER M4 ;
        RECT  0 118.272 0.084 118.296 ;
    END
  END w[53]
  PIN w[54]
    DIRECTION INPUT ;
    USE SIGNAL ;
    PORT
      LAYER M4 ;
        RECT  0 118.08 0.084 118.104 ;
    END
  END w[54]
  PIN w[55]
    DIRECTION INPUT ;
    USE SIGNAL ;
    PORT
      LAYER M4 ;
        RECT  0 117.504 0.084 117.528 ;
    END
  END w[55]
  PIN w[56]
    DIRECTION INPUT ;
    USE SIGNAL ;
    PORT
      LAYER M4 ;
        RECT  0 115.584 0.084 115.608 ;
    END
  END w[56]
  PIN w[57]
    DIRECTION INPUT ;
    USE SIGNAL ;
    PORT
      LAYER M4 ;
        RECT  0 113.76 0.084 113.784 ;
    END
  END w[57]
  PIN w[58]
    DIRECTION INPUT ;
    USE SIGNAL ;
    PORT
      LAYER M4 ;
        RECT  0 113.472 0.084 113.496 ;
    END
  END w[58]
  PIN w[59]
    DIRECTION INPUT ;
    USE SIGNAL ;
    PORT
      LAYER M4 ;
        RECT  0 110.88 0.084 110.904 ;
    END
  END w[59]
  PIN w[5]
    DIRECTION INPUT ;
    USE SIGNAL ;
    PORT
      LAYER M5 ;
        RECT  14.496 196.504 14.52 196.588 ;
    END
  END w[5]
  PIN w[60]
    DIRECTION INPUT ;
    USE SIGNAL ;
    PORT
      LAYER M4 ;
        RECT  0 109.536 0.084 109.56 ;
    END
  END w[60]
  PIN w[61]
    DIRECTION INPUT ;
    USE SIGNAL ;
    PORT
      LAYER M4 ;
        RECT  0 109.44 0.084 109.464 ;
    END
  END w[61]
  PIN w[62]
    DIRECTION INPUT ;
    USE SIGNAL ;
    PORT
      LAYER M4 ;
        RECT  0 107.52 0.084 107.544 ;
    END
  END w[62]
  PIN w[63]
    DIRECTION INPUT ;
    USE SIGNAL ;
    PORT
      LAYER M4 ;
        RECT  0 103.872 0.084 103.896 ;
    END
  END w[63]
  PIN w[64]
    DIRECTION INPUT ;
    USE SIGNAL ;
    PORT
      LAYER M4 ;
        RECT  0 138.432 0.084 138.456 ;
    END
  END w[64]
  PIN w[65]
    DIRECTION INPUT ;
    USE SIGNAL ;
    PORT
      LAYER M4 ;
        RECT  0 139.392 0.084 139.416 ;
    END
  END w[65]
  PIN w[66]
    DIRECTION INPUT ;
    USE SIGNAL ;
    PORT
      LAYER M4 ;
        RECT  0 139.104 0.084 139.128 ;
    END
  END w[66]
  PIN w[67]
    DIRECTION INPUT ;
    USE SIGNAL ;
    PORT
      LAYER M4 ;
        RECT  0 139.296 0.084 139.32 ;
    END
  END w[67]
  PIN w[68]
    DIRECTION INPUT ;
    USE SIGNAL ;
    PORT
      LAYER M4 ;
        RECT  0 140.928 0.084 140.952 ;
    END
  END w[68]
  PIN w[69]
    DIRECTION INPUT ;
    USE SIGNAL ;
    PORT
      LAYER M4 ;
        RECT  0 141.6 0.084 141.624 ;
    END
  END w[69]
  PIN w[6]
    DIRECTION INPUT ;
    USE SIGNAL ;
    PORT
      LAYER M5 ;
        RECT  13.728 196.504 13.752 196.588 ;
    END
  END w[6]
  PIN w[70]
    DIRECTION INPUT ;
    USE SIGNAL ;
    PORT
      LAYER M4 ;
        RECT  0 142.08 0.084 142.104 ;
    END
  END w[70]
  PIN w[71]
    DIRECTION INPUT ;
    USE SIGNAL ;
    PORT
      LAYER M4 ;
        RECT  0 143.52 0.084 143.544 ;
    END
  END w[71]
  PIN w[72]
    DIRECTION INPUT ;
    USE SIGNAL ;
    PORT
      LAYER M4 ;
        RECT  0 145.248 0.084 145.272 ;
    END
  END w[72]
  PIN w[73]
    DIRECTION INPUT ;
    USE SIGNAL ;
    PORT
      LAYER M4 ;
        RECT  0 146.304 0.084 146.328 ;
    END
  END w[73]
  PIN w[74]
    DIRECTION INPUT ;
    USE SIGNAL ;
    PORT
      LAYER M4 ;
        RECT  0 147.936 0.084 147.96 ;
    END
  END w[74]
  PIN w[75]
    DIRECTION INPUT ;
    USE SIGNAL ;
    PORT
      LAYER M4 ;
        RECT  0 148.032 0.084 148.056 ;
    END
  END w[75]
  PIN w[76]
    DIRECTION INPUT ;
    USE SIGNAL ;
    PORT
      LAYER M4 ;
        RECT  0 153.312 0.084 153.336 ;
    END
  END w[76]
  PIN w[77]
    DIRECTION INPUT ;
    USE SIGNAL ;
    PORT
      LAYER M4 ;
        RECT  0 153.408 0.084 153.432 ;
    END
  END w[77]
  PIN w[78]
    DIRECTION INPUT ;
    USE SIGNAL ;
    PORT
      LAYER M5 ;
        RECT  31.488 196.504 31.512 196.588 ;
    END
  END w[78]
  PIN w[79]
    DIRECTION INPUT ;
    USE SIGNAL ;
    PORT
      LAYER M5 ;
        RECT  108.384 196.504 108.408 196.588 ;
    END
  END w[79]
  PIN w[7]
    DIRECTION INPUT ;
    USE SIGNAL ;
    PORT
      LAYER M5 ;
        RECT  20.64 196.504 20.664 196.588 ;
    END
  END w[7]
  PIN w[80]
    DIRECTION INPUT ;
    USE SIGNAL ;
    PORT
      LAYER M5 ;
        RECT  35.328 196.504 35.352 196.588 ;
    END
  END w[80]
  PIN w[81]
    DIRECTION INPUT ;
    USE SIGNAL ;
    PORT
      LAYER M5 ;
        RECT  35.424 196.504 35.448 196.588 ;
    END
  END w[81]
  PIN w[82]
    DIRECTION INPUT ;
    USE SIGNAL ;
    PORT
      LAYER M5 ;
        RECT  35.52 196.504 35.544 196.588 ;
    END
  END w[82]
  PIN w[83]
    DIRECTION INPUT ;
    USE SIGNAL ;
    PORT
      LAYER M5 ;
        RECT  35.232 196.504 35.256 196.588 ;
    END
  END w[83]
  PIN w[84]
    DIRECTION INPUT ;
    USE SIGNAL ;
    PORT
      LAYER M5 ;
        RECT  36.96 196.504 36.984 196.588 ;
    END
  END w[84]
  PIN w[85]
    DIRECTION INPUT ;
    USE SIGNAL ;
    PORT
      LAYER M5 ;
        RECT  35.712 196.504 35.736 196.588 ;
    END
  END w[85]
  PIN w[86]
    DIRECTION INPUT ;
    USE SIGNAL ;
    PORT
      LAYER M5 ;
        RECT  38.208 196.504 38.232 196.588 ;
    END
  END w[86]
  PIN w[87]
    DIRECTION INPUT ;
    USE SIGNAL ;
    PORT
      LAYER M5 ;
        RECT  38.496 196.504 38.52 196.588 ;
    END
  END w[87]
  PIN w[88]
    DIRECTION INPUT ;
    USE SIGNAL ;
    PORT
      LAYER M5 ;
        RECT  40.032 196.504 40.056 196.588 ;
    END
  END w[88]
  PIN w[89]
    DIRECTION INPUT ;
    USE SIGNAL ;
    PORT
      LAYER M5 ;
        RECT  39.072 196.504 39.096 196.588 ;
    END
  END w[89]
  PIN w[8]
    DIRECTION INPUT ;
    USE SIGNAL ;
    PORT
      LAYER M5 ;
        RECT  21.12 196.504 21.144 196.588 ;
    END
  END w[8]
  PIN w[90]
    DIRECTION INPUT ;
    USE SIGNAL ;
    PORT
      LAYER M5 ;
        RECT  40.416 196.504 40.44 196.588 ;
    END
  END w[90]
  PIN w[91]
    DIRECTION INPUT ;
    USE SIGNAL ;
    PORT
      LAYER M5 ;
        RECT  40.704 196.504 40.728 196.588 ;
    END
  END w[91]
  PIN w[92]
    DIRECTION INPUT ;
    USE SIGNAL ;
    PORT
      LAYER M5 ;
        RECT  42.048 196.504 42.072 196.588 ;
    END
  END w[92]
  PIN w[93]
    DIRECTION INPUT ;
    USE SIGNAL ;
    PORT
      LAYER M5 ;
        RECT  41.856 196.504 41.88 196.588 ;
    END
  END w[93]
  PIN w[94]
    DIRECTION INPUT ;
    USE SIGNAL ;
    PORT
      LAYER M5 ;
        RECT  42.912 196.504 42.936 196.588 ;
    END
  END w[94]
  PIN w[95]
    DIRECTION INPUT ;
    USE SIGNAL ;
    PORT
      LAYER M5 ;
        RECT  66.912 196.504 66.936 196.588 ;
    END
  END w[95]
  PIN w[96]
    DIRECTION INPUT ;
    USE SIGNAL ;
    PORT
      LAYER M4 ;
        RECT  0 48.768 0.084 48.792 ;
    END
  END w[96]
  PIN w[97]
    DIRECTION INPUT ;
    USE SIGNAL ;
    PORT
      LAYER M4 ;
        RECT  0 47.52 0.084 47.544 ;
    END
  END w[97]
  PIN w[98]
    DIRECTION INPUT ;
    USE SIGNAL ;
    PORT
      LAYER M4 ;
        RECT  0 51.936 0.084 51.96 ;
    END
  END w[98]
  PIN w[99]
    DIRECTION INPUT ;
    USE SIGNAL ;
    PORT
      LAYER M4 ;
        RECT  0 51.456 0.084 51.48 ;
    END
  END w[99]
  PIN w[9]
    DIRECTION INPUT ;
    USE SIGNAL ;
    PORT
      LAYER M5 ;
        RECT  21.408 196.504 21.432 196.588 ;
    END
  END w[9]
  PIN x[0]
    DIRECTION INPUT ;
    USE SIGNAL ;
    PORT
      LAYER M5 ;
        RECT  15.84 196.504 15.864 196.588 ;
    END
  END x[0]
  PIN x[100]
    DIRECTION INPUT ;
    USE SIGNAL ;
    PORT
      LAYER M4 ;
        RECT  0 54.048 0.084 54.072 ;
    END
  END x[100]
  PIN x[101]
    DIRECTION INPUT ;
    USE SIGNAL ;
    PORT
      LAYER M4 ;
        RECT  0 54.72 0.084 54.744 ;
    END
  END x[101]
  PIN x[102]
    DIRECTION INPUT ;
    USE SIGNAL ;
    PORT
      LAYER M4 ;
        RECT  0 54.624 0.084 54.648 ;
    END
  END x[102]
  PIN x[103]
    DIRECTION INPUT ;
    USE SIGNAL ;
    PORT
      LAYER M4 ;
        RECT  0 55.2 0.084 55.224 ;
    END
  END x[103]
  PIN x[104]
    DIRECTION INPUT ;
    USE SIGNAL ;
    PORT
      LAYER M4 ;
        RECT  0 55.296 0.084 55.32 ;
    END
  END x[104]
  PIN x[105]
    DIRECTION INPUT ;
    USE SIGNAL ;
    PORT
      LAYER M4 ;
        RECT  0 55.104 0.084 55.128 ;
    END
  END x[105]
  PIN x[106]
    DIRECTION INPUT ;
    USE SIGNAL ;
    PORT
      LAYER M4 ;
        RECT  0 55.392 0.084 55.416 ;
    END
  END x[106]
  PIN x[107]
    DIRECTION INPUT ;
    USE SIGNAL ;
    PORT
      LAYER M4 ;
        RECT  0 55.68 0.084 55.704 ;
    END
  END x[107]
  PIN x[108]
    DIRECTION INPUT ;
    USE SIGNAL ;
    PORT
      LAYER M4 ;
        RECT  0 55.584 0.084 55.608 ;
    END
  END x[108]
  PIN x[109]
    DIRECTION INPUT ;
    USE SIGNAL ;
    PORT
      LAYER M4 ;
        RECT  0 55.488 0.084 55.512 ;
    END
  END x[109]
  PIN x[10]
    DIRECTION INPUT ;
    USE SIGNAL ;
    PORT
      LAYER M5 ;
        RECT  17.952 196.504 17.976 196.588 ;
    END
  END x[10]
  PIN x[110]
    DIRECTION INPUT ;
    USE SIGNAL ;
    PORT
      LAYER M4 ;
        RECT  0 54.528 0.084 54.552 ;
    END
  END x[110]
  PIN x[111]
    DIRECTION INPUT ;
    USE SIGNAL ;
    PORT
      LAYER M4 ;
        RECT  0 58.656 0.084 58.68 ;
    END
  END x[111]
  PIN x[112]
    DIRECTION INPUT ;
    USE SIGNAL ;
    PORT
      LAYER M4 ;
        RECT  0 52.704 0.084 52.728 ;
    END
  END x[112]
  PIN x[113]
    DIRECTION INPUT ;
    USE SIGNAL ;
    PORT
      LAYER M4 ;
        RECT  0 56.832 0.084 56.856 ;
    END
  END x[113]
  PIN x[114]
    DIRECTION INPUT ;
    USE SIGNAL ;
    PORT
      LAYER M4 ;
        RECT  0 57.408 0.084 57.432 ;
    END
  END x[114]
  PIN x[115]
    DIRECTION INPUT ;
    USE SIGNAL ;
    PORT
      LAYER M4 ;
        RECT  0 57.504 0.084 57.528 ;
    END
  END x[115]
  PIN x[116]
    DIRECTION INPUT ;
    USE SIGNAL ;
    PORT
      LAYER M4 ;
        RECT  0 56.544 0.084 56.568 ;
    END
  END x[116]
  PIN x[117]
    DIRECTION INPUT ;
    USE SIGNAL ;
    PORT
      LAYER M4 ;
        RECT  0 57.888 0.084 57.912 ;
    END
  END x[117]
  PIN x[118]
    DIRECTION INPUT ;
    USE SIGNAL ;
    PORT
      LAYER M4 ;
        RECT  0 58.176 0.084 58.2 ;
    END
  END x[118]
  PIN x[119]
    DIRECTION INPUT ;
    USE SIGNAL ;
    PORT
      LAYER M4 ;
        RECT  0 54.912 0.084 54.936 ;
    END
  END x[119]
  PIN x[11]
    DIRECTION INPUT ;
    USE SIGNAL ;
    PORT
      LAYER M5 ;
        RECT  18.144 196.504 18.168 196.588 ;
    END
  END x[11]
  PIN x[120]
    DIRECTION INPUT ;
    USE SIGNAL ;
    PORT
      LAYER M4 ;
        RECT  0 56.16 0.084 56.184 ;
    END
  END x[120]
  PIN x[121]
    DIRECTION INPUT ;
    USE SIGNAL ;
    PORT
      LAYER M4 ;
        RECT  0 55.968 0.084 55.992 ;
    END
  END x[121]
  PIN x[122]
    DIRECTION INPUT ;
    USE SIGNAL ;
    PORT
      LAYER M4 ;
        RECT  0 56.064 0.084 56.088 ;
    END
  END x[122]
  PIN x[123]
    DIRECTION INPUT ;
    USE SIGNAL ;
    PORT
      LAYER M4 ;
        RECT  0 57.024 0.084 57.048 ;
    END
  END x[123]
  PIN x[124]
    DIRECTION INPUT ;
    USE SIGNAL ;
    PORT
      LAYER M4 ;
        RECT  0 57.696 0.084 57.72 ;
    END
  END x[124]
  PIN x[125]
    DIRECTION INPUT ;
    USE SIGNAL ;
    PORT
      LAYER M4 ;
        RECT  0 57.984 0.084 58.008 ;
    END
  END x[125]
  PIN x[126]
    DIRECTION INPUT ;
    USE SIGNAL ;
    PORT
      LAYER M4 ;
        RECT  0 61.728 0.084 61.752 ;
    END
  END x[126]
  PIN x[127]
    DIRECTION INPUT ;
    USE SIGNAL ;
    PORT
      LAYER M4 ;
        RECT  0 71.616 0.084 71.64 ;
    END
  END x[127]
  PIN x[128]
    DIRECTION INPUT ;
    USE SIGNAL ;
    PORT
      LAYER M5 ;
        RECT  51.168 0 51.192 0.084 ;
    END
  END x[128]
  PIN x[129]
    DIRECTION INPUT ;
    USE SIGNAL ;
    PORT
      LAYER M5 ;
        RECT  51.744 0 51.768 0.084 ;
    END
  END x[129]
  PIN x[12]
    DIRECTION INPUT ;
    USE SIGNAL ;
    PORT
      LAYER M5 ;
        RECT  18.432 196.504 18.456 196.588 ;
    END
  END x[12]
  PIN x[130]
    DIRECTION INPUT ;
    USE SIGNAL ;
    PORT
      LAYER M5 ;
        RECT  51.264 0 51.288 0.084 ;
    END
  END x[130]
  PIN x[131]
    DIRECTION INPUT ;
    USE SIGNAL ;
    PORT
      LAYER M5 ;
        RECT  51.552 0 51.576 0.084 ;
    END
  END x[131]
  PIN x[132]
    DIRECTION INPUT ;
    USE SIGNAL ;
    PORT
      LAYER M5 ;
        RECT  51.84 0 51.864 0.084 ;
    END
  END x[132]
  PIN x[133]
    DIRECTION INPUT ;
    USE SIGNAL ;
    PORT
      LAYER M5 ;
        RECT  50.976 0 51 0.084 ;
    END
  END x[133]
  PIN x[134]
    DIRECTION INPUT ;
    USE SIGNAL ;
    PORT
      LAYER M5 ;
        RECT  52.896 0 52.92 0.084 ;
    END
  END x[134]
  PIN x[135]
    DIRECTION INPUT ;
    USE SIGNAL ;
    PORT
      LAYER M5 ;
        RECT  52.512 0 52.536 0.084 ;
    END
  END x[135]
  PIN x[136]
    DIRECTION INPUT ;
    USE SIGNAL ;
    PORT
      LAYER M5 ;
        RECT  52.608 0 52.632 0.084 ;
    END
  END x[136]
  PIN x[137]
    DIRECTION INPUT ;
    USE SIGNAL ;
    PORT
      LAYER M5 ;
        RECT  52.8 0 52.824 0.084 ;
    END
  END x[137]
  PIN x[138]
    DIRECTION INPUT ;
    USE SIGNAL ;
    PORT
      LAYER M5 ;
        RECT  52.704 0 52.728 0.084 ;
    END
  END x[138]
  PIN x[139]
    DIRECTION INPUT ;
    USE SIGNAL ;
    PORT
      LAYER M5 ;
        RECT  52.32 0 52.344 0.084 ;
    END
  END x[139]
  PIN x[13]
    DIRECTION INPUT ;
    USE SIGNAL ;
    PORT
      LAYER M5 ;
        RECT  18.528 196.504 18.552 196.588 ;
    END
  END x[13]
  PIN x[140]
    DIRECTION INPUT ;
    USE SIGNAL ;
    PORT
      LAYER M5 ;
        RECT  53.856 0 53.88 0.084 ;
    END
  END x[140]
  PIN x[141]
    DIRECTION INPUT ;
    USE SIGNAL ;
    PORT
      LAYER M5 ;
        RECT  53.952 0 53.976 0.084 ;
    END
  END x[141]
  PIN x[142]
    DIRECTION INPUT ;
    USE SIGNAL ;
    PORT
      LAYER M5 ;
        RECT  55.104 0 55.128 0.084 ;
    END
  END x[142]
  PIN x[143]
    DIRECTION INPUT ;
    USE SIGNAL ;
    PORT
      LAYER M5 ;
        RECT  167.52 0 167.544 0.084 ;
    END
  END x[143]
  PIN x[144]
    DIRECTION INPUT ;
    USE SIGNAL ;
    PORT
      LAYER M4 ;
        RECT  0 94.656 0.084 94.68 ;
    END
  END x[144]
  PIN x[145]
    DIRECTION INPUT ;
    USE SIGNAL ;
    PORT
      LAYER M4 ;
        RECT  0 95.136 0.084 95.16 ;
    END
  END x[145]
  PIN x[146]
    DIRECTION INPUT ;
    USE SIGNAL ;
    PORT
      LAYER M4 ;
        RECT  0 97.152 0.084 97.176 ;
    END
  END x[146]
  PIN x[147]
    DIRECTION INPUT ;
    USE SIGNAL ;
    PORT
      LAYER M4 ;
        RECT  0 96.096 0.084 96.12 ;
    END
  END x[147]
  PIN x[148]
    DIRECTION INPUT ;
    USE SIGNAL ;
    PORT
      LAYER M4 ;
        RECT  0 98.496 0.084 98.52 ;
    END
  END x[148]
  PIN x[149]
    DIRECTION INPUT ;
    USE SIGNAL ;
    PORT
      LAYER M4 ;
        RECT  0 98.208 0.084 98.232 ;
    END
  END x[149]
  PIN x[14]
    DIRECTION INPUT ;
    USE SIGNAL ;
    PORT
      LAYER M5 ;
        RECT  21.216 196.504 21.24 196.588 ;
    END
  END x[14]
  PIN x[150]
    DIRECTION INPUT ;
    USE SIGNAL ;
    PORT
      LAYER M4 ;
        RECT  0 98.304 0.084 98.328 ;
    END
  END x[150]
  PIN x[151]
    DIRECTION INPUT ;
    USE SIGNAL ;
    PORT
      LAYER M4 ;
        RECT  0 99.552 0.084 99.576 ;
    END
  END x[151]
  PIN x[152]
    DIRECTION INPUT ;
    USE SIGNAL ;
    PORT
      LAYER M4 ;
        RECT  0 99.936 0.084 99.96 ;
    END
  END x[152]
  PIN x[153]
    DIRECTION INPUT ;
    USE SIGNAL ;
    PORT
      LAYER M4 ;
        RECT  0 100.032 0.084 100.056 ;
    END
  END x[153]
  PIN x[154]
    DIRECTION INPUT ;
    USE SIGNAL ;
    PORT
      LAYER M4 ;
        RECT  0 100.128 0.084 100.152 ;
    END
  END x[154]
  PIN x[155]
    DIRECTION INPUT ;
    USE SIGNAL ;
    PORT
      LAYER M4 ;
        RECT  0 101.184 0.084 101.208 ;
    END
  END x[155]
  PIN x[156]
    DIRECTION INPUT ;
    USE SIGNAL ;
    PORT
      LAYER M4 ;
        RECT  0 101.76 0.084 101.784 ;
    END
  END x[156]
  PIN x[157]
    DIRECTION INPUT ;
    USE SIGNAL ;
    PORT
      LAYER M4 ;
        RECT  0 103.392 0.084 103.416 ;
    END
  END x[157]
  PIN x[158]
    DIRECTION INPUT ;
    USE SIGNAL ;
    PORT
      LAYER M4 ;
        RECT  0 103.2 0.084 103.224 ;
    END
  END x[158]
  PIN x[159]
    DIRECTION INPUT ;
    USE SIGNAL ;
    PORT
      LAYER M4 ;
        RECT  0 89.568 0.084 89.592 ;
    END
  END x[159]
  PIN x[15]
    DIRECTION INPUT ;
    USE SIGNAL ;
    PORT
      LAYER M5 ;
        RECT  39.84 196.504 39.864 196.588 ;
    END
  END x[15]
  PIN x[160]
    DIRECTION INPUT ;
    USE SIGNAL ;
    PORT
      LAYER M5 ;
        RECT  27.936 196.504 27.96 196.588 ;
    END
  END x[160]
  PIN x[161]
    DIRECTION INPUT ;
    USE SIGNAL ;
    PORT
      LAYER M5 ;
        RECT  24.096 196.504 24.12 196.588 ;
    END
  END x[161]
  PIN x[162]
    DIRECTION INPUT ;
    USE SIGNAL ;
    PORT
      LAYER M5 ;
        RECT  24.192 196.504 24.216 196.588 ;
    END
  END x[162]
  PIN x[163]
    DIRECTION INPUT ;
    USE SIGNAL ;
    PORT
      LAYER M5 ;
        RECT  23.616 196.504 23.64 196.588 ;
    END
  END x[163]
  PIN x[164]
    DIRECTION INPUT ;
    USE SIGNAL ;
    PORT
      LAYER M5 ;
        RECT  27.168 196.504 27.192 196.588 ;
    END
  END x[164]
  PIN x[165]
    DIRECTION INPUT ;
    USE SIGNAL ;
    PORT
      LAYER M4 ;
        RECT  0 173.856 0.084 173.88 ;
    END
  END x[165]
  PIN x[166]
    DIRECTION INPUT ;
    USE SIGNAL ;
    PORT
      LAYER M4 ;
        RECT  0 173.76 0.084 173.784 ;
    END
  END x[166]
  PIN x[167]
    DIRECTION INPUT ;
    USE SIGNAL ;
    PORT
      LAYER M5 ;
        RECT  27.84 196.504 27.864 196.588 ;
    END
  END x[167]
  PIN x[168]
    DIRECTION INPUT ;
    USE SIGNAL ;
    PORT
      LAYER M5 ;
        RECT  28.512 196.504 28.536 196.588 ;
    END
  END x[168]
  PIN x[169]
    DIRECTION INPUT ;
    USE SIGNAL ;
    PORT
      LAYER M5 ;
        RECT  29.088 196.504 29.112 196.588 ;
    END
  END x[169]
  PIN x[16]
    DIRECTION INPUT ;
    USE SIGNAL ;
    PORT
      LAYER M4 ;
        RECT  0 122.496 0.084 122.52 ;
    END
  END x[16]
  PIN x[170]
    DIRECTION INPUT ;
    USE SIGNAL ;
    PORT
      LAYER M5 ;
        RECT  29.184 196.504 29.208 196.588 ;
    END
  END x[170]
  PIN x[171]
    DIRECTION INPUT ;
    USE SIGNAL ;
    PORT
      LAYER M5 ;
        RECT  29.28 196.504 29.304 196.588 ;
    END
  END x[171]
  PIN x[172]
    DIRECTION INPUT ;
    USE SIGNAL ;
    PORT
      LAYER M5 ;
        RECT  30.048 196.504 30.072 196.588 ;
    END
  END x[172]
  PIN x[173]
    DIRECTION INPUT ;
    USE SIGNAL ;
    PORT
      LAYER M5 ;
        RECT  31.296 196.504 31.32 196.588 ;
    END
  END x[173]
  PIN x[174]
    DIRECTION INPUT ;
    USE SIGNAL ;
    PORT
      LAYER M5 ;
        RECT  30.24 196.504 30.264 196.588 ;
    END
  END x[174]
  PIN x[175]
    DIRECTION INPUT ;
    USE SIGNAL ;
    PORT
      LAYER M5 ;
        RECT  77.856 196.504 77.88 196.588 ;
    END
  END x[175]
  PIN x[176]
    DIRECTION INPUT ;
    USE SIGNAL ;
    PORT
      LAYER M4 ;
        RECT  0 114.24 0.084 114.264 ;
    END
  END x[176]
  PIN x[177]
    DIRECTION INPUT ;
    USE SIGNAL ;
    PORT
      LAYER M4 ;
        RECT  0 115.392 0.084 115.416 ;
    END
  END x[177]
  PIN x[178]
    DIRECTION INPUT ;
    USE SIGNAL ;
    PORT
      LAYER M4 ;
        RECT  0 115.872 0.084 115.896 ;
    END
  END x[178]
  PIN x[179]
    DIRECTION INPUT ;
    USE SIGNAL ;
    PORT
      LAYER M4 ;
        RECT  0 116.832 0.084 116.856 ;
    END
  END x[179]
  PIN x[17]
    DIRECTION INPUT ;
    USE SIGNAL ;
    PORT
      LAYER M4 ;
        RECT  0 123.264 0.084 123.288 ;
    END
  END x[17]
  PIN x[180]
    DIRECTION INPUT ;
    USE SIGNAL ;
    PORT
      LAYER M4 ;
        RECT  0 116.928 0.084 116.952 ;
    END
  END x[180]
  PIN x[181]
    DIRECTION INPUT ;
    USE SIGNAL ;
    PORT
      LAYER M4 ;
        RECT  0 116.64 0.084 116.664 ;
    END
  END x[181]
  PIN x[182]
    DIRECTION INPUT ;
    USE SIGNAL ;
    PORT
      LAYER M4 ;
        RECT  0 115.968 0.084 115.992 ;
    END
  END x[182]
  PIN x[183]
    DIRECTION INPUT ;
    USE SIGNAL ;
    PORT
      LAYER M4 ;
        RECT  0 117.12 0.084 117.144 ;
    END
  END x[183]
  PIN x[184]
    DIRECTION INPUT ;
    USE SIGNAL ;
    PORT
      LAYER M4 ;
        RECT  0 117.216 0.084 117.24 ;
    END
  END x[184]
  PIN x[185]
    DIRECTION INPUT ;
    USE SIGNAL ;
    PORT
      LAYER M4 ;
        RECT  0 117.408 0.084 117.432 ;
    END
  END x[185]
  PIN x[186]
    DIRECTION INPUT ;
    USE SIGNAL ;
    PORT
      LAYER M4 ;
        RECT  0 117.312 0.084 117.336 ;
    END
  END x[186]
  PIN x[187]
    DIRECTION INPUT ;
    USE SIGNAL ;
    PORT
      LAYER M4 ;
        RECT  0 117.024 0.084 117.048 ;
    END
  END x[187]
  PIN x[188]
    DIRECTION INPUT ;
    USE SIGNAL ;
    PORT
      LAYER M4 ;
        RECT  0 114.72 0.084 114.744 ;
    END
  END x[188]
  PIN x[189]
    DIRECTION INPUT ;
    USE SIGNAL ;
    PORT
      LAYER M4 ;
        RECT  0 114.624 0.084 114.648 ;
    END
  END x[189]
  PIN x[18]
    DIRECTION INPUT ;
    USE SIGNAL ;
    PORT
      LAYER M4 ;
        RECT  0 122.592 0.084 122.616 ;
    END
  END x[18]
  PIN x[190]
    DIRECTION INPUT ;
    USE SIGNAL ;
    PORT
      LAYER M4 ;
        RECT  0 113.376 0.084 113.4 ;
    END
  END x[190]
  PIN x[191]
    DIRECTION INPUT ;
    USE SIGNAL ;
    PORT
      LAYER M4 ;
        RECT  0 126.048 0.084 126.072 ;
    END
  END x[191]
  PIN x[192]
    DIRECTION INPUT ;
    USE SIGNAL ;
    PORT
      LAYER M4 ;
        RECT  0 36.96 0.084 36.984 ;
    END
  END x[192]
  PIN x[193]
    DIRECTION INPUT ;
    USE SIGNAL ;
    PORT
      LAYER M4 ;
        RECT  0 37.152 0.084 37.176 ;
    END
  END x[193]
  PIN x[194]
    DIRECTION INPUT ;
    USE SIGNAL ;
    PORT
      LAYER M4 ;
        RECT  0 36.672 0.084 36.696 ;
    END
  END x[194]
  PIN x[195]
    DIRECTION INPUT ;
    USE SIGNAL ;
    PORT
      LAYER M4 ;
        RECT  0 34.08 0.084 34.104 ;
    END
  END x[195]
  PIN x[196]
    DIRECTION INPUT ;
    USE SIGNAL ;
    PORT
      LAYER M4 ;
        RECT  0 33.984 0.084 34.008 ;
    END
  END x[196]
  PIN x[197]
    DIRECTION INPUT ;
    USE SIGNAL ;
    PORT
      LAYER M4 ;
        RECT  0 38.304 0.084 38.328 ;
    END
  END x[197]
  PIN x[198]
    DIRECTION INPUT ;
    USE SIGNAL ;
    PORT
      LAYER M4 ;
        RECT  0 39.456 0.084 39.48 ;
    END
  END x[198]
  PIN x[199]
    DIRECTION INPUT ;
    USE SIGNAL ;
    PORT
      LAYER M4 ;
        RECT  0 38.208 0.084 38.232 ;
    END
  END x[199]
  PIN x[19]
    DIRECTION INPUT ;
    USE SIGNAL ;
    PORT
      LAYER M4 ;
        RECT  0 122.88 0.084 122.904 ;
    END
  END x[19]
  PIN x[1]
    DIRECTION INPUT ;
    USE SIGNAL ;
    PORT
      LAYER M5 ;
        RECT  15.744 196.504 15.768 196.588 ;
    END
  END x[1]
  PIN x[200]
    DIRECTION INPUT ;
    USE SIGNAL ;
    PORT
      LAYER M4 ;
        RECT  0 38.784 0.084 38.808 ;
    END
  END x[200]
  PIN x[201]
    DIRECTION INPUT ;
    USE SIGNAL ;
    PORT
      LAYER M4 ;
        RECT  0 38.688 0.084 38.712 ;
    END
  END x[201]
  PIN x[202]
    DIRECTION INPUT ;
    USE SIGNAL ;
    PORT
      LAYER M4 ;
        RECT  0 39.264 0.084 39.288 ;
    END
  END x[202]
  PIN x[203]
    DIRECTION INPUT ;
    USE SIGNAL ;
    PORT
      LAYER M4 ;
        RECT  0 41.568 0.084 41.592 ;
    END
  END x[203]
  PIN x[204]
    DIRECTION INPUT ;
    USE SIGNAL ;
    PORT
      LAYER M4 ;
        RECT  0 40.704 0.084 40.728 ;
    END
  END x[204]
  PIN x[205]
    DIRECTION INPUT ;
    USE SIGNAL ;
    PORT
      LAYER M4 ;
        RECT  0 42.816 0.084 42.84 ;
    END
  END x[205]
  PIN x[206]
    DIRECTION INPUT ;
    USE SIGNAL ;
    PORT
      LAYER M4 ;
        RECT  0 43.104 0.084 43.128 ;
    END
  END x[206]
  PIN x[207]
    DIRECTION INPUT ;
    USE SIGNAL ;
    PORT
      LAYER M4 ;
        RECT  0 37.248 0.084 37.272 ;
    END
  END x[207]
  PIN x[208]
    DIRECTION INPUT ;
    USE SIGNAL ;
    PORT
      LAYER M4 ;
        RECT  0 106.272 0.084 106.296 ;
    END
  END x[208]
  PIN x[209]
    DIRECTION INPUT ;
    USE SIGNAL ;
    PORT
      LAYER M4 ;
        RECT  0 108.48 0.084 108.504 ;
    END
  END x[209]
  PIN x[20]
    DIRECTION INPUT ;
    USE SIGNAL ;
    PORT
      LAYER M4 ;
        RECT  0 124.896 0.084 124.92 ;
    END
  END x[20]
  PIN x[210]
    DIRECTION INPUT ;
    USE SIGNAL ;
    PORT
      LAYER M4 ;
        RECT  0 108.192 0.084 108.216 ;
    END
  END x[210]
  PIN x[211]
    DIRECTION INPUT ;
    USE SIGNAL ;
    PORT
      LAYER M4 ;
        RECT  0 108.288 0.084 108.312 ;
    END
  END x[211]
  PIN x[212]
    DIRECTION INPUT ;
    USE SIGNAL ;
    PORT
      LAYER M4 ;
        RECT  0 107.232 0.084 107.256 ;
    END
  END x[212]
  PIN x[213]
    DIRECTION INPUT ;
    USE SIGNAL ;
    PORT
      LAYER M4 ;
        RECT  0 107.712 0.084 107.736 ;
    END
  END x[213]
  PIN x[214]
    DIRECTION INPUT ;
    USE SIGNAL ;
    PORT
      LAYER M4 ;
        RECT  0 107.04 0.084 107.064 ;
    END
  END x[214]
  PIN x[215]
    DIRECTION INPUT ;
    USE SIGNAL ;
    PORT
      LAYER M4 ;
        RECT  0 106.848 0.084 106.872 ;
    END
  END x[215]
  PIN x[216]
    DIRECTION INPUT ;
    USE SIGNAL ;
    PORT
      LAYER M4 ;
        RECT  0 106.944 0.084 106.968 ;
    END
  END x[216]
  PIN x[217]
    DIRECTION INPUT ;
    USE SIGNAL ;
    PORT
      LAYER M4 ;
        RECT  0 106.752 0.084 106.776 ;
    END
  END x[217]
  PIN x[218]
    DIRECTION INPUT ;
    USE SIGNAL ;
    PORT
      LAYER M4 ;
        RECT  0 107.136 0.084 107.16 ;
    END
  END x[218]
  PIN x[219]
    DIRECTION INPUT ;
    USE SIGNAL ;
    PORT
      LAYER M4 ;
        RECT  0 106.464 0.084 106.488 ;
    END
  END x[219]
  PIN x[21]
    DIRECTION INPUT ;
    USE SIGNAL ;
    PORT
      LAYER M4 ;
        RECT  0 121.92 0.084 121.944 ;
    END
  END x[21]
  PIN x[220]
    DIRECTION INPUT ;
    USE SIGNAL ;
    PORT
      LAYER M4 ;
        RECT  0 106.656 0.084 106.68 ;
    END
  END x[220]
  PIN x[221]
    DIRECTION INPUT ;
    USE SIGNAL ;
    PORT
      LAYER M4 ;
        RECT  0 106.56 0.084 106.584 ;
    END
  END x[221]
  PIN x[222]
    DIRECTION INPUT ;
    USE SIGNAL ;
    PORT
      LAYER M4 ;
        RECT  0 106.368 0.084 106.392 ;
    END
  END x[222]
  PIN x[223]
    DIRECTION INPUT ;
    USE SIGNAL ;
    PORT
      LAYER M4 ;
        RECT  0 102.336 0.084 102.36 ;
    END
  END x[223]
  PIN x[224]
    DIRECTION INPUT ;
    USE SIGNAL ;
    PORT
      LAYER M5 ;
        RECT  20.352 0 20.376 0.084 ;
    END
  END x[224]
  PIN x[225]
    DIRECTION INPUT ;
    USE SIGNAL ;
    PORT
      LAYER M5 ;
        RECT  20.448 0 20.472 0.084 ;
    END
  END x[225]
  PIN x[226]
    DIRECTION INPUT ;
    USE SIGNAL ;
    PORT
      LAYER M5 ;
        RECT  20.16 0 20.184 0.084 ;
    END
  END x[226]
  PIN x[227]
    DIRECTION INPUT ;
    USE SIGNAL ;
    PORT
      LAYER M5 ;
        RECT  20.544 0 20.568 0.084 ;
    END
  END x[227]
  PIN x[228]
    DIRECTION INPUT ;
    USE SIGNAL ;
    PORT
      LAYER M5 ;
        RECT  20.928 0 20.952 0.084 ;
    END
  END x[228]
  PIN x[229]
    DIRECTION INPUT ;
    USE SIGNAL ;
    PORT
      LAYER M5 ;
        RECT  20.64 0 20.664 0.084 ;
    END
  END x[229]
  PIN x[22]
    DIRECTION INPUT ;
    USE SIGNAL ;
    PORT
      LAYER M4 ;
        RECT  0 124.416 0.084 124.44 ;
    END
  END x[22]
  PIN x[230]
    DIRECTION INPUT ;
    USE SIGNAL ;
    PORT
      LAYER M5 ;
        RECT  21.12 0 21.144 0.084 ;
    END
  END x[230]
  PIN x[231]
    DIRECTION INPUT ;
    USE SIGNAL ;
    PORT
      LAYER M5 ;
        RECT  21.312 0 21.336 0.084 ;
    END
  END x[231]
  PIN x[232]
    DIRECTION INPUT ;
    USE SIGNAL ;
    PORT
      LAYER M5 ;
        RECT  25.344 0 25.368 0.084 ;
    END
  END x[232]
  PIN x[233]
    DIRECTION INPUT ;
    USE SIGNAL ;
    PORT
      LAYER M5 ;
        RECT  28.992 0 29.016 0.084 ;
    END
  END x[233]
  PIN x[234]
    DIRECTION INPUT ;
    USE SIGNAL ;
    PORT
      LAYER M5 ;
        RECT  27.36 0 27.384 0.084 ;
    END
  END x[234]
  PIN x[235]
    DIRECTION INPUT ;
    USE SIGNAL ;
    PORT
      LAYER M5 ;
        RECT  27.456 0 27.48 0.084 ;
    END
  END x[235]
  PIN x[236]
    DIRECTION INPUT ;
    USE SIGNAL ;
    PORT
      LAYER M5 ;
        RECT  30.144 0 30.168 0.084 ;
    END
  END x[236]
  PIN x[237]
    DIRECTION INPUT ;
    USE SIGNAL ;
    PORT
      LAYER M5 ;
        RECT  30.048 0 30.072 0.084 ;
    END
  END x[237]
  PIN x[238]
    DIRECTION INPUT ;
    USE SIGNAL ;
    PORT
      LAYER M5 ;
        RECT  31.68 0 31.704 0.084 ;
    END
  END x[238]
  PIN x[239]
    DIRECTION INPUT ;
    USE SIGNAL ;
    PORT
      LAYER M5 ;
        RECT  38.784 0 38.808 0.084 ;
    END
  END x[239]
  PIN x[23]
    DIRECTION INPUT ;
    USE SIGNAL ;
    PORT
      LAYER M4 ;
        RECT  0 129.888 0.084 129.912 ;
    END
  END x[23]
  PIN x[240]
    DIRECTION INPUT ;
    USE SIGNAL ;
    PORT
      LAYER M4 ;
        RECT  0 62.976 0.084 63 ;
    END
  END x[240]
  PIN x[241]
    DIRECTION INPUT ;
    USE SIGNAL ;
    PORT
      LAYER M4 ;
        RECT  0 62.304 0.084 62.328 ;
    END
  END x[241]
  PIN x[242]
    DIRECTION INPUT ;
    USE SIGNAL ;
    PORT
      LAYER M4 ;
        RECT  0 61.152 0.084 61.176 ;
    END
  END x[242]
  PIN x[243]
    DIRECTION INPUT ;
    USE SIGNAL ;
    PORT
      LAYER M4 ;
        RECT  0 61.92 0.084 61.944 ;
    END
  END x[243]
  PIN x[244]
    DIRECTION INPUT ;
    USE SIGNAL ;
    PORT
      LAYER M4 ;
        RECT  0 61.056 0.084 61.08 ;
    END
  END x[244]
  PIN x[245]
    DIRECTION INPUT ;
    USE SIGNAL ;
    PORT
      LAYER M4 ;
        RECT  0 62.016 0.084 62.04 ;
    END
  END x[245]
  PIN x[246]
    DIRECTION INPUT ;
    USE SIGNAL ;
    PORT
      LAYER M4 ;
        RECT  0 62.4 0.084 62.424 ;
    END
  END x[246]
  PIN x[247]
    DIRECTION INPUT ;
    USE SIGNAL ;
    PORT
      LAYER M4 ;
        RECT  0 57.312 0.084 57.336 ;
    END
  END x[247]
  PIN x[248]
    DIRECTION INPUT ;
    USE SIGNAL ;
    PORT
      LAYER M4 ;
        RECT  0 57.792 0.084 57.816 ;
    END
  END x[248]
  PIN x[249]
    DIRECTION INPUT ;
    USE SIGNAL ;
    PORT
      LAYER M4 ;
        RECT  0 58.08 0.084 58.104 ;
    END
  END x[249]
  PIN x[24]
    DIRECTION INPUT ;
    USE SIGNAL ;
    PORT
      LAYER M4 ;
        RECT  0 132.48 0.084 132.504 ;
    END
  END x[24]
  PIN x[250]
    DIRECTION INPUT ;
    USE SIGNAL ;
    PORT
      LAYER M4 ;
        RECT  0 58.272 0.084 58.296 ;
    END
  END x[250]
  PIN x[251]
    DIRECTION INPUT ;
    USE SIGNAL ;
    PORT
      LAYER M4 ;
        RECT  0 58.368 0.084 58.392 ;
    END
  END x[251]
  PIN x[252]
    DIRECTION INPUT ;
    USE SIGNAL ;
    PORT
      LAYER M4 ;
        RECT  0 56.928 0.084 56.952 ;
    END
  END x[252]
  PIN x[253]
    DIRECTION INPUT ;
    USE SIGNAL ;
    PORT
      LAYER M4 ;
        RECT  0 56.448 0.084 56.472 ;
    END
  END x[253]
  PIN x[254]
    DIRECTION INPUT ;
    USE SIGNAL ;
    PORT
      LAYER M4 ;
        RECT  0 55.872 0.084 55.896 ;
    END
  END x[254]
  PIN x[255]
    DIRECTION INPUT ;
    USE SIGNAL ;
    PORT
      LAYER M4 ;
        RECT  0 51.84 0.084 51.864 ;
    END
  END x[255]
  PIN x[25]
    DIRECTION INPUT ;
    USE SIGNAL ;
    PORT
      LAYER M4 ;
        RECT  0 132.768 0.084 132.792 ;
    END
  END x[25]
  PIN x[26]
    DIRECTION INPUT ;
    USE SIGNAL ;
    PORT
      LAYER M4 ;
        RECT  0 133.056 0.084 133.08 ;
    END
  END x[26]
  PIN x[27]
    DIRECTION INPUT ;
    USE SIGNAL ;
    PORT
      LAYER M4 ;
        RECT  0 133.824 0.084 133.848 ;
    END
  END x[27]
  PIN x[28]
    DIRECTION INPUT ;
    USE SIGNAL ;
    PORT
      LAYER M4 ;
        RECT  0 132.864 0.084 132.888 ;
    END
  END x[28]
  PIN x[29]
    DIRECTION INPUT ;
    USE SIGNAL ;
    PORT
      LAYER M4 ;
        RECT  0 135.168 0.084 135.192 ;
    END
  END x[29]
  PIN x[2]
    DIRECTION INPUT ;
    USE SIGNAL ;
    PORT
      LAYER M5 ;
        RECT  15.36 196.504 15.384 196.588 ;
    END
  END x[2]
  PIN x[30]
    DIRECTION INPUT ;
    USE SIGNAL ;
    PORT
      LAYER M4 ;
        RECT  0 135.264 0.084 135.288 ;
    END
  END x[30]
  PIN x[31]
    DIRECTION INPUT ;
    USE SIGNAL ;
    PORT
      LAYER M4 ;
        RECT  0 124.224 0.084 124.248 ;
    END
  END x[31]
  PIN x[32]
    DIRECTION INPUT ;
    USE SIGNAL ;
    PORT
      LAYER M4 ;
        RECT  0 82.176 0.084 82.2 ;
    END
  END x[32]
  PIN x[33]
    DIRECTION INPUT ;
    USE SIGNAL ;
    PORT
      LAYER M4 ;
        RECT  0 83.712 0.084 83.736 ;
    END
  END x[33]
  PIN x[34]
    DIRECTION INPUT ;
    USE SIGNAL ;
    PORT
      LAYER M4 ;
        RECT  0 80.256 0.084 80.28 ;
    END
  END x[34]
  PIN x[35]
    DIRECTION INPUT ;
    USE SIGNAL ;
    PORT
      LAYER M4 ;
        RECT  0 79.296 0.084 79.32 ;
    END
  END x[35]
  PIN x[36]
    DIRECTION INPUT ;
    USE SIGNAL ;
    PORT
      LAYER M4 ;
        RECT  0 82.848 0.084 82.872 ;
    END
  END x[36]
  PIN x[37]
    DIRECTION INPUT ;
    USE SIGNAL ;
    PORT
      LAYER M4 ;
        RECT  0 83.232 0.084 83.256 ;
    END
  END x[37]
  PIN x[38]
    DIRECTION INPUT ;
    USE SIGNAL ;
    PORT
      LAYER M4 ;
        RECT  0 83.616 0.084 83.64 ;
    END
  END x[38]
  PIN x[39]
    DIRECTION INPUT ;
    USE SIGNAL ;
    PORT
      LAYER M4 ;
        RECT  0 84.192 0.084 84.216 ;
    END
  END x[39]
  PIN x[3]
    DIRECTION INPUT ;
    USE SIGNAL ;
    PORT
      LAYER M5 ;
        RECT  15.936 196.504 15.96 196.588 ;
    END
  END x[3]
  PIN x[40]
    DIRECTION INPUT ;
    USE SIGNAL ;
    PORT
      LAYER M4 ;
        RECT  0 84.288 0.084 84.312 ;
    END
  END x[40]
  PIN x[41]
    DIRECTION INPUT ;
    USE SIGNAL ;
    PORT
      LAYER M4 ;
        RECT  0 84.384 0.084 84.408 ;
    END
  END x[41]
  PIN x[42]
    DIRECTION INPUT ;
    USE SIGNAL ;
    PORT
      LAYER M4 ;
        RECT  0 85.056 0.084 85.08 ;
    END
  END x[42]
  PIN x[43]
    DIRECTION INPUT ;
    USE SIGNAL ;
    PORT
      LAYER M4 ;
        RECT  0 84.672 0.084 84.696 ;
    END
  END x[43]
  PIN x[44]
    DIRECTION INPUT ;
    USE SIGNAL ;
    PORT
      LAYER M4 ;
        RECT  0 86.304 0.084 86.328 ;
    END
  END x[44]
  PIN x[45]
    DIRECTION INPUT ;
    USE SIGNAL ;
    PORT
      LAYER M4 ;
        RECT  0 86.4 0.084 86.424 ;
    END
  END x[45]
  PIN x[46]
    DIRECTION INPUT ;
    USE SIGNAL ;
    PORT
      LAYER M4 ;
        RECT  0 86.976 0.084 87 ;
    END
  END x[46]
  PIN x[47]
    DIRECTION INPUT ;
    USE SIGNAL ;
    PORT
      LAYER M5 ;
        RECT  128.16 0 128.184 0.084 ;
    END
  END x[47]
  PIN x[48]
    DIRECTION INPUT ;
    USE SIGNAL ;
    PORT
      LAYER M4 ;
        RECT  0 114.144 0.084 114.168 ;
    END
  END x[48]
  PIN x[49]
    DIRECTION INPUT ;
    USE SIGNAL ;
    PORT
      LAYER M4 ;
        RECT  0 113.184 0.084 113.208 ;
    END
  END x[49]
  PIN x[4]
    DIRECTION INPUT ;
    USE SIGNAL ;
    PORT
      LAYER M5 ;
        RECT  16.224 196.504 16.248 196.588 ;
    END
  END x[4]
  PIN x[50]
    DIRECTION INPUT ;
    USE SIGNAL ;
    PORT
      LAYER M4 ;
        RECT  0 113.664 0.084 113.688 ;
    END
  END x[50]
  PIN x[51]
    DIRECTION INPUT ;
    USE SIGNAL ;
    PORT
      LAYER M4 ;
        RECT  0 113.088 0.084 113.112 ;
    END
  END x[51]
  PIN x[52]
    DIRECTION INPUT ;
    USE SIGNAL ;
    PORT
      LAYER M4 ;
        RECT  0 112.512 0.084 112.536 ;
    END
  END x[52]
  PIN x[53]
    DIRECTION INPUT ;
    USE SIGNAL ;
    PORT
      LAYER M4 ;
        RECT  0 115.68 0.084 115.704 ;
    END
  END x[53]
  PIN x[54]
    DIRECTION INPUT ;
    USE SIGNAL ;
    PORT
      LAYER M4 ;
        RECT  0 112.704 0.084 112.728 ;
    END
  END x[54]
  PIN x[55]
    DIRECTION INPUT ;
    USE SIGNAL ;
    PORT
      LAYER M4 ;
        RECT  0 112.416 0.084 112.44 ;
    END
  END x[55]
  PIN x[56]
    DIRECTION INPUT ;
    USE SIGNAL ;
    PORT
      LAYER M4 ;
        RECT  0 112.608 0.084 112.632 ;
    END
  END x[56]
  PIN x[57]
    DIRECTION INPUT ;
    USE SIGNAL ;
    PORT
      LAYER M4 ;
        RECT  0 112.32 0.084 112.344 ;
    END
  END x[57]
  PIN x[58]
    DIRECTION INPUT ;
    USE SIGNAL ;
    PORT
      LAYER M4 ;
        RECT  0 111.84 0.084 111.864 ;
    END
  END x[58]
  PIN x[59]
    DIRECTION INPUT ;
    USE SIGNAL ;
    PORT
      LAYER M4 ;
        RECT  0 110.784 0.084 110.808 ;
    END
  END x[59]
  PIN x[5]
    DIRECTION INPUT ;
    USE SIGNAL ;
    PORT
      LAYER M5 ;
        RECT  16.32 196.504 16.344 196.588 ;
    END
  END x[5]
  PIN x[60]
    DIRECTION INPUT ;
    USE SIGNAL ;
    PORT
      LAYER M4 ;
        RECT  0 108.384 0.084 108.408 ;
    END
  END x[60]
  PIN x[61]
    DIRECTION INPUT ;
    USE SIGNAL ;
    PORT
      LAYER M4 ;
        RECT  0 108.096 0.084 108.12 ;
    END
  END x[61]
  PIN x[62]
    DIRECTION INPUT ;
    USE SIGNAL ;
    PORT
      LAYER M4 ;
        RECT  0 107.808 0.084 107.832 ;
    END
  END x[62]
  PIN x[63]
    DIRECTION INPUT ;
    USE SIGNAL ;
    PORT
      LAYER M4 ;
        RECT  0 103.776 0.084 103.8 ;
    END
  END x[63]
  PIN x[64]
    DIRECTION INPUT ;
    USE SIGNAL ;
    PORT
      LAYER M4 ;
        RECT  0 136.512 0.084 136.536 ;
    END
  END x[64]
  PIN x[65]
    DIRECTION INPUT ;
    USE SIGNAL ;
    PORT
      LAYER M4 ;
        RECT  0 137.856 0.084 137.88 ;
    END
  END x[65]
  PIN x[66]
    DIRECTION INPUT ;
    USE SIGNAL ;
    PORT
      LAYER M4 ;
        RECT  0 137.664 0.084 137.688 ;
    END
  END x[66]
  PIN x[67]
    DIRECTION INPUT ;
    USE SIGNAL ;
    PORT
      LAYER M4 ;
        RECT  0 136.704 0.084 136.728 ;
    END
  END x[67]
  PIN x[68]
    DIRECTION INPUT ;
    USE SIGNAL ;
    PORT
      LAYER M4 ;
        RECT  0 138.816 0.084 138.84 ;
    END
  END x[68]
  PIN x[69]
    DIRECTION INPUT ;
    USE SIGNAL ;
    PORT
      LAYER M4 ;
        RECT  0 137.376 0.084 137.4 ;
    END
  END x[69]
  PIN x[6]
    DIRECTION INPUT ;
    USE SIGNAL ;
    PORT
      LAYER M5 ;
        RECT  17.76 196.504 17.784 196.588 ;
    END
  END x[6]
  PIN x[70]
    DIRECTION INPUT ;
    USE SIGNAL ;
    PORT
      LAYER M4 ;
        RECT  0 139.968 0.084 139.992 ;
    END
  END x[70]
  PIN x[71]
    DIRECTION INPUT ;
    USE SIGNAL ;
    PORT
      LAYER M4 ;
        RECT  0 143.232 0.084 143.256 ;
    END
  END x[71]
  PIN x[72]
    DIRECTION INPUT ;
    USE SIGNAL ;
    PORT
      LAYER M4 ;
        RECT  0 149.952 0.084 149.976 ;
    END
  END x[72]
  PIN x[73]
    DIRECTION INPUT ;
    USE SIGNAL ;
    PORT
      LAYER M4 ;
        RECT  0 149.664 0.084 149.688 ;
    END
  END x[73]
  PIN x[74]
    DIRECTION INPUT ;
    USE SIGNAL ;
    PORT
      LAYER M4 ;
        RECT  0 149.472 0.084 149.496 ;
    END
  END x[74]
  PIN x[75]
    DIRECTION INPUT ;
    USE SIGNAL ;
    PORT
      LAYER M4 ;
        RECT  0 150.528 0.084 150.552 ;
    END
  END x[75]
  PIN x[76]
    DIRECTION INPUT ;
    USE SIGNAL ;
    PORT
      LAYER M4 ;
        RECT  0 151.488 0.084 151.512 ;
    END
  END x[76]
  PIN x[77]
    DIRECTION INPUT ;
    USE SIGNAL ;
    PORT
      LAYER M4 ;
        RECT  0 149.376 0.084 149.4 ;
    END
  END x[77]
  PIN x[78]
    DIRECTION INPUT ;
    USE SIGNAL ;
    PORT
      LAYER M4 ;
        RECT  0 149.568 0.084 149.592 ;
    END
  END x[78]
  PIN x[79]
    DIRECTION INPUT ;
    USE SIGNAL ;
    PORT
      LAYER M5 ;
        RECT  108.192 196.504 108.216 196.588 ;
    END
  END x[79]
  PIN x[7]
    DIRECTION INPUT ;
    USE SIGNAL ;
    PORT
      LAYER M5 ;
        RECT  17.28 196.504 17.304 196.588 ;
    END
  END x[7]
  PIN x[80]
    DIRECTION INPUT ;
    USE SIGNAL ;
    PORT
      LAYER M5 ;
        RECT  33.984 196.504 34.008 196.588 ;
    END
  END x[80]
  PIN x[81]
    DIRECTION INPUT ;
    USE SIGNAL ;
    PORT
      LAYER M5 ;
        RECT  34.752 196.504 34.776 196.588 ;
    END
  END x[81]
  PIN x[82]
    DIRECTION INPUT ;
    USE SIGNAL ;
    PORT
      LAYER M5 ;
        RECT  34.176 196.504 34.2 196.588 ;
    END
  END x[82]
  PIN x[83]
    DIRECTION INPUT ;
    USE SIGNAL ;
    PORT
      LAYER M5 ;
        RECT  33.888 196.504 33.912 196.588 ;
    END
  END x[83]
  PIN x[84]
    DIRECTION INPUT ;
    USE SIGNAL ;
    PORT
      LAYER M5 ;
        RECT  35.616 196.504 35.64 196.588 ;
    END
  END x[84]
  PIN x[85]
    DIRECTION INPUT ;
    USE SIGNAL ;
    PORT
      LAYER M5 ;
        RECT  34.944 196.504 34.968 196.588 ;
    END
  END x[85]
  PIN x[86]
    DIRECTION INPUT ;
    USE SIGNAL ;
    PORT
      LAYER M5 ;
        RECT  36.096 196.504 36.12 196.588 ;
    END
  END x[86]
  PIN x[87]
    DIRECTION INPUT ;
    USE SIGNAL ;
    PORT
      LAYER M5 ;
        RECT  37.632 196.504 37.656 196.588 ;
    END
  END x[87]
  PIN x[88]
    DIRECTION INPUT ;
    USE SIGNAL ;
    PORT
      LAYER M5 ;
        RECT  38.016 196.504 38.04 196.588 ;
    END
  END x[88]
  PIN x[89]
    DIRECTION INPUT ;
    USE SIGNAL ;
    PORT
      LAYER M5 ;
        RECT  38.784 196.504 38.808 196.588 ;
    END
  END x[89]
  PIN x[8]
    DIRECTION INPUT ;
    USE SIGNAL ;
    PORT
      LAYER M5 ;
        RECT  17.856 196.504 17.88 196.588 ;
    END
  END x[8]
  PIN x[90]
    DIRECTION INPUT ;
    USE SIGNAL ;
    PORT
      LAYER M5 ;
        RECT  38.976 196.504 39 196.588 ;
    END
  END x[90]
  PIN x[91]
    DIRECTION INPUT ;
    USE SIGNAL ;
    PORT
      LAYER M5 ;
        RECT  39.264 196.504 39.288 196.588 ;
    END
  END x[91]
  PIN x[92]
    DIRECTION INPUT ;
    USE SIGNAL ;
    PORT
      LAYER M5 ;
        RECT  40.32 196.504 40.344 196.588 ;
    END
  END x[92]
  PIN x[93]
    DIRECTION INPUT ;
    USE SIGNAL ;
    PORT
      LAYER M5 ;
        RECT  40.224 196.504 40.248 196.588 ;
    END
  END x[93]
  PIN x[94]
    DIRECTION INPUT ;
    USE SIGNAL ;
    PORT
      LAYER M5 ;
        RECT  40.896 196.504 40.92 196.588 ;
    END
  END x[94]
  PIN x[95]
    DIRECTION INPUT ;
    USE SIGNAL ;
    PORT
      LAYER M5 ;
        RECT  66.816 196.504 66.84 196.588 ;
    END
  END x[95]
  PIN x[96]
    DIRECTION INPUT ;
    USE SIGNAL ;
    PORT
      LAYER M4 ;
        RECT  0 54.816 0.084 54.84 ;
    END
  END x[96]
  PIN x[97]
    DIRECTION INPUT ;
    USE SIGNAL ;
    PORT
      LAYER M4 ;
        RECT  0 55.008 0.084 55.032 ;
    END
  END x[97]
  PIN x[98]
    DIRECTION INPUT ;
    USE SIGNAL ;
    PORT
      LAYER M4 ;
        RECT  0 54.144 0.084 54.168 ;
    END
  END x[98]
  PIN x[99]
    DIRECTION INPUT ;
    USE SIGNAL ;
    PORT
      LAYER M4 ;
        RECT  0 53.952 0.084 53.976 ;
    END
  END x[99]
  PIN x[9]
    DIRECTION INPUT ;
    USE SIGNAL ;
    PORT
      LAYER M5 ;
        RECT  18.048 196.504 18.072 196.588 ;
    END
  END x[9]
  PIN y[0]
    DIRECTION OUTPUT ;
    USE SIGNAL ;
    PORT
      LAYER M4 ;
        RECT  196.504 127.584 196.588 127.608 ;
    END
  END y[0]
  PIN y[10]
    DIRECTION OUTPUT ;
    USE SIGNAL ;
    PORT
      LAYER M4 ;
        RECT  196.504 122.304 196.588 122.328 ;
    END
  END y[10]
  PIN y[11]
    DIRECTION OUTPUT ;
    USE SIGNAL ;
    PORT
      LAYER M4 ;
        RECT  196.504 121.248 196.588 121.272 ;
    END
  END y[11]
  PIN y[12]
    DIRECTION OUTPUT ;
    USE SIGNAL ;
    PORT
      LAYER M4 ;
        RECT  196.504 116.448 196.588 116.472 ;
    END
  END y[12]
  PIN y[13]
    DIRECTION OUTPUT ;
    USE SIGNAL ;
    PORT
      LAYER M4 ;
        RECT  196.504 115.104 196.588 115.128 ;
    END
  END y[13]
  PIN y[14]
    DIRECTION OUTPUT ;
    USE SIGNAL ;
    PORT
      LAYER M4 ;
        RECT  196.504 120.48 196.588 120.504 ;
    END
  END y[14]
  PIN y[15]
    DIRECTION OUTPUT ;
    USE SIGNAL ;
    PORT
      LAYER M4 ;
        RECT  196.504 119.616 196.588 119.64 ;
    END
  END y[15]
  PIN y[16]
    DIRECTION OUTPUT ;
    USE SIGNAL ;
    PORT
      LAYER M4 ;
        RECT  196.504 118.752 196.588 118.776 ;
    END
  END y[16]
  PIN y[17]
    DIRECTION OUTPUT ;
    USE SIGNAL ;
    PORT
      LAYER M4 ;
        RECT  196.504 115.2 196.588 115.224 ;
    END
  END y[17]
  PIN y[18]
    DIRECTION OUTPUT ;
    USE SIGNAL ;
    PORT
      LAYER M4 ;
        RECT  196.504 114.048 196.588 114.072 ;
    END
  END y[18]
  PIN y[19]
    DIRECTION OUTPUT ;
    USE SIGNAL ;
    PORT
      LAYER M4 ;
        RECT  196.504 113.28 196.588 113.304 ;
    END
  END y[19]
  PIN y[1]
    DIRECTION OUTPUT ;
    USE SIGNAL ;
    PORT
      LAYER M4 ;
        RECT  196.504 131.712 196.588 131.736 ;
    END
  END y[1]
  PIN y[20]
    DIRECTION OUTPUT ;
    USE SIGNAL ;
    PORT
      LAYER M4 ;
        RECT  196.504 116.928 196.588 116.952 ;
    END
  END y[20]
  PIN y[21]
    DIRECTION OUTPUT ;
    USE SIGNAL ;
    PORT
      LAYER M4 ;
        RECT  196.504 117.888 196.588 117.912 ;
    END
  END y[21]
  PIN y[22]
    DIRECTION OUTPUT ;
    USE SIGNAL ;
    PORT
      LAYER M4 ;
        RECT  196.504 134.208 196.588 134.232 ;
    END
  END y[22]
  PIN y[23]
    DIRECTION OUTPUT ;
    USE SIGNAL ;
    PORT
      LAYER M4 ;
        RECT  196.504 135.168 196.588 135.192 ;
    END
  END y[23]
  PIN y[24]
    DIRECTION OUTPUT ;
    USE SIGNAL ;
    PORT
      LAYER M4 ;
        RECT  196.504 136.8 196.588 136.824 ;
    END
  END y[24]
  PIN y[25]
    DIRECTION OUTPUT ;
    USE SIGNAL ;
    PORT
      LAYER M4 ;
        RECT  196.504 138.624 196.588 138.648 ;
    END
  END y[25]
  PIN y[26]
    DIRECTION OUTPUT ;
    USE SIGNAL ;
    PORT
      LAYER M4 ;
        RECT  196.504 138.336 196.588 138.36 ;
    END
  END y[26]
  PIN y[27]
    DIRECTION OUTPUT ;
    USE SIGNAL ;
    PORT
      LAYER M4 ;
        RECT  196.504 135.552 196.588 135.576 ;
    END
  END y[27]
  PIN y[28]
    DIRECTION OUTPUT ;
    USE SIGNAL ;
    PORT
      LAYER M4 ;
        RECT  196.504 136.704 196.588 136.728 ;
    END
  END y[28]
  PIN y[29]
    DIRECTION OUTPUT ;
    USE SIGNAL ;
    PORT
      LAYER M4 ;
        RECT  196.504 137.856 196.588 137.88 ;
    END
  END y[29]
  PIN y[2]
    DIRECTION OUTPUT ;
    USE SIGNAL ;
    PORT
      LAYER M4 ;
        RECT  196.504 128.352 196.588 128.376 ;
    END
  END y[2]
  PIN y[30]
    DIRECTION OUTPUT ;
    USE SIGNAL ;
    PORT
      LAYER M4 ;
        RECT  196.504 139.008 196.588 139.032 ;
    END
  END y[30]
  PIN y[31]
    DIRECTION OUTPUT ;
    USE SIGNAL ;
    PORT
      LAYER M4 ;
        RECT  196.504 134.592 196.588 134.616 ;
    END
  END y[31]
  PIN y[3]
    DIRECTION OUTPUT ;
    USE SIGNAL ;
    PORT
      LAYER M4 ;
        RECT  196.504 133.632 196.588 133.656 ;
    END
  END y[3]
  PIN y[4]
    DIRECTION OUTPUT ;
    USE SIGNAL ;
    PORT
      LAYER M4 ;
        RECT  196.504 130.368 196.588 130.392 ;
    END
  END y[4]
  PIN y[5]
    DIRECTION OUTPUT ;
    USE SIGNAL ;
    PORT
      LAYER M4 ;
        RECT  196.504 129.312 196.588 129.336 ;
    END
  END y[5]
  PIN y[6]
    DIRECTION OUTPUT ;
    USE SIGNAL ;
    PORT
      LAYER M4 ;
        RECT  196.504 129.216 196.588 129.24 ;
    END
  END y[6]
  PIN y[7]
    DIRECTION OUTPUT ;
    USE SIGNAL ;
    PORT
      LAYER M4 ;
        RECT  196.504 130.656 196.588 130.68 ;
    END
  END y[7]
  PIN y[8]
    DIRECTION OUTPUT ;
    USE SIGNAL ;
    PORT
      LAYER M4 ;
        RECT  196.504 126.912 196.588 126.936 ;
    END
  END y[8]
  PIN y[9]
    DIRECTION OUTPUT ;
    USE SIGNAL ;
    PORT
      LAYER M4 ;
        RECT  196.504 123.552 196.588 123.576 ;
    END
  END y[9]
  PIN VDD
    DIRECTION INOUT ;
    USE POWER ;
    PORT
      LAYER M6 ;
        RECT  1.44 188 195.174 188.288 ;
        RECT  1.44 177.2 195.174 177.488 ;
        RECT  1.44 166.4 195.174 166.688 ;
        RECT  1.44 155.6 195.174 155.888 ;
        RECT  1.44 144.8 195.174 145.088 ;
        RECT  1.44 134 195.174 134.288 ;
        RECT  1.44 123.2 195.174 123.488 ;
        RECT  1.44 112.4 195.174 112.688 ;
        RECT  1.44 101.6 195.174 101.888 ;
        RECT  1.44 90.8 195.174 91.088 ;
        RECT  1.44 80 195.174 80.288 ;
        RECT  1.44 69.2 195.174 69.488 ;
        RECT  1.44 58.4 195.174 58.688 ;
        RECT  1.44 47.6 195.174 47.888 ;
        RECT  1.44 36.8 195.174 37.088 ;
        RECT  1.44 26 195.174 26.288 ;
        RECT  1.44 15.2 195.174 15.488 ;
        RECT  1.44 4.4 195.174 4.688 ;
        RECT  1.44 195.084 195.174 195.372 ;
        RECT  1.44 1.188 195.174 1.476 ;
    END
  END VDD
  PIN VSS
    DIRECTION INOUT ;
    USE GROUND ;
    PORT
      LAYER M6 ;
        RECT  1.44 187.616 195.174 187.904 ;
        RECT  1.44 176.816 195.174 177.104 ;
        RECT  1.44 166.016 195.174 166.304 ;
        RECT  1.44 155.216 195.174 155.504 ;
        RECT  1.44 144.416 195.174 144.704 ;
        RECT  1.44 133.616 195.174 133.904 ;
        RECT  1.44 122.816 195.174 123.104 ;
        RECT  1.44 112.016 195.174 112.304 ;
        RECT  1.44 101.216 195.174 101.504 ;
        RECT  1.44 90.416 195.174 90.704 ;
        RECT  1.44 79.616 195.174 79.904 ;
        RECT  1.44 68.816 195.174 69.104 ;
        RECT  1.44 58.016 195.174 58.304 ;
        RECT  1.44 47.216 195.174 47.504 ;
        RECT  1.44 36.416 195.174 36.704 ;
        RECT  1.44 25.616 195.174 25.904 ;
        RECT  1.44 14.816 195.174 15.104 ;
        RECT  1.44 4.016 195.174 4.304 ;
        RECT  1.632 194.7 194.982 194.988 ;
        RECT  1.632 1.572 194.982 1.86 ;
    END
  END VSS
  OBS
    LAYER RVTN ;
     RECT  0 0 196.588 196.588 ;
    LAYER RVTP ;
     RECT  0 0 196.588 196.588 ;
    LAYER M1 ;
     RECT  0 0 196.588 196.588 ;
    LAYER M2 ;
     RECT  0 0 196.588 196.588 ;
    LAYER M3 ;
     RECT  0 0 196.588 196.588 ;
    LAYER M4 ;
     RECT  0 0 196.588 196.588 ;
    LAYER M5 ;
     RECT  0 0 196.588 196.588 ;
    LAYER M6 ;
     RECT  0 0 196.588 196.588 ;
  END
END ot_hbm_accel_tc16
END LIBRARY
